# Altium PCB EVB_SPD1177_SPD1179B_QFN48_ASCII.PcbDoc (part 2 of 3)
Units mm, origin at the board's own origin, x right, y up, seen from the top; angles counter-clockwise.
Board outline 135 x 90 mm, 4 copper layers (Top Layer, GND, L3, Bottom Layer), stack 0.603 mm thick; 320 components, 157 nets, 728 pads, 938 vias.

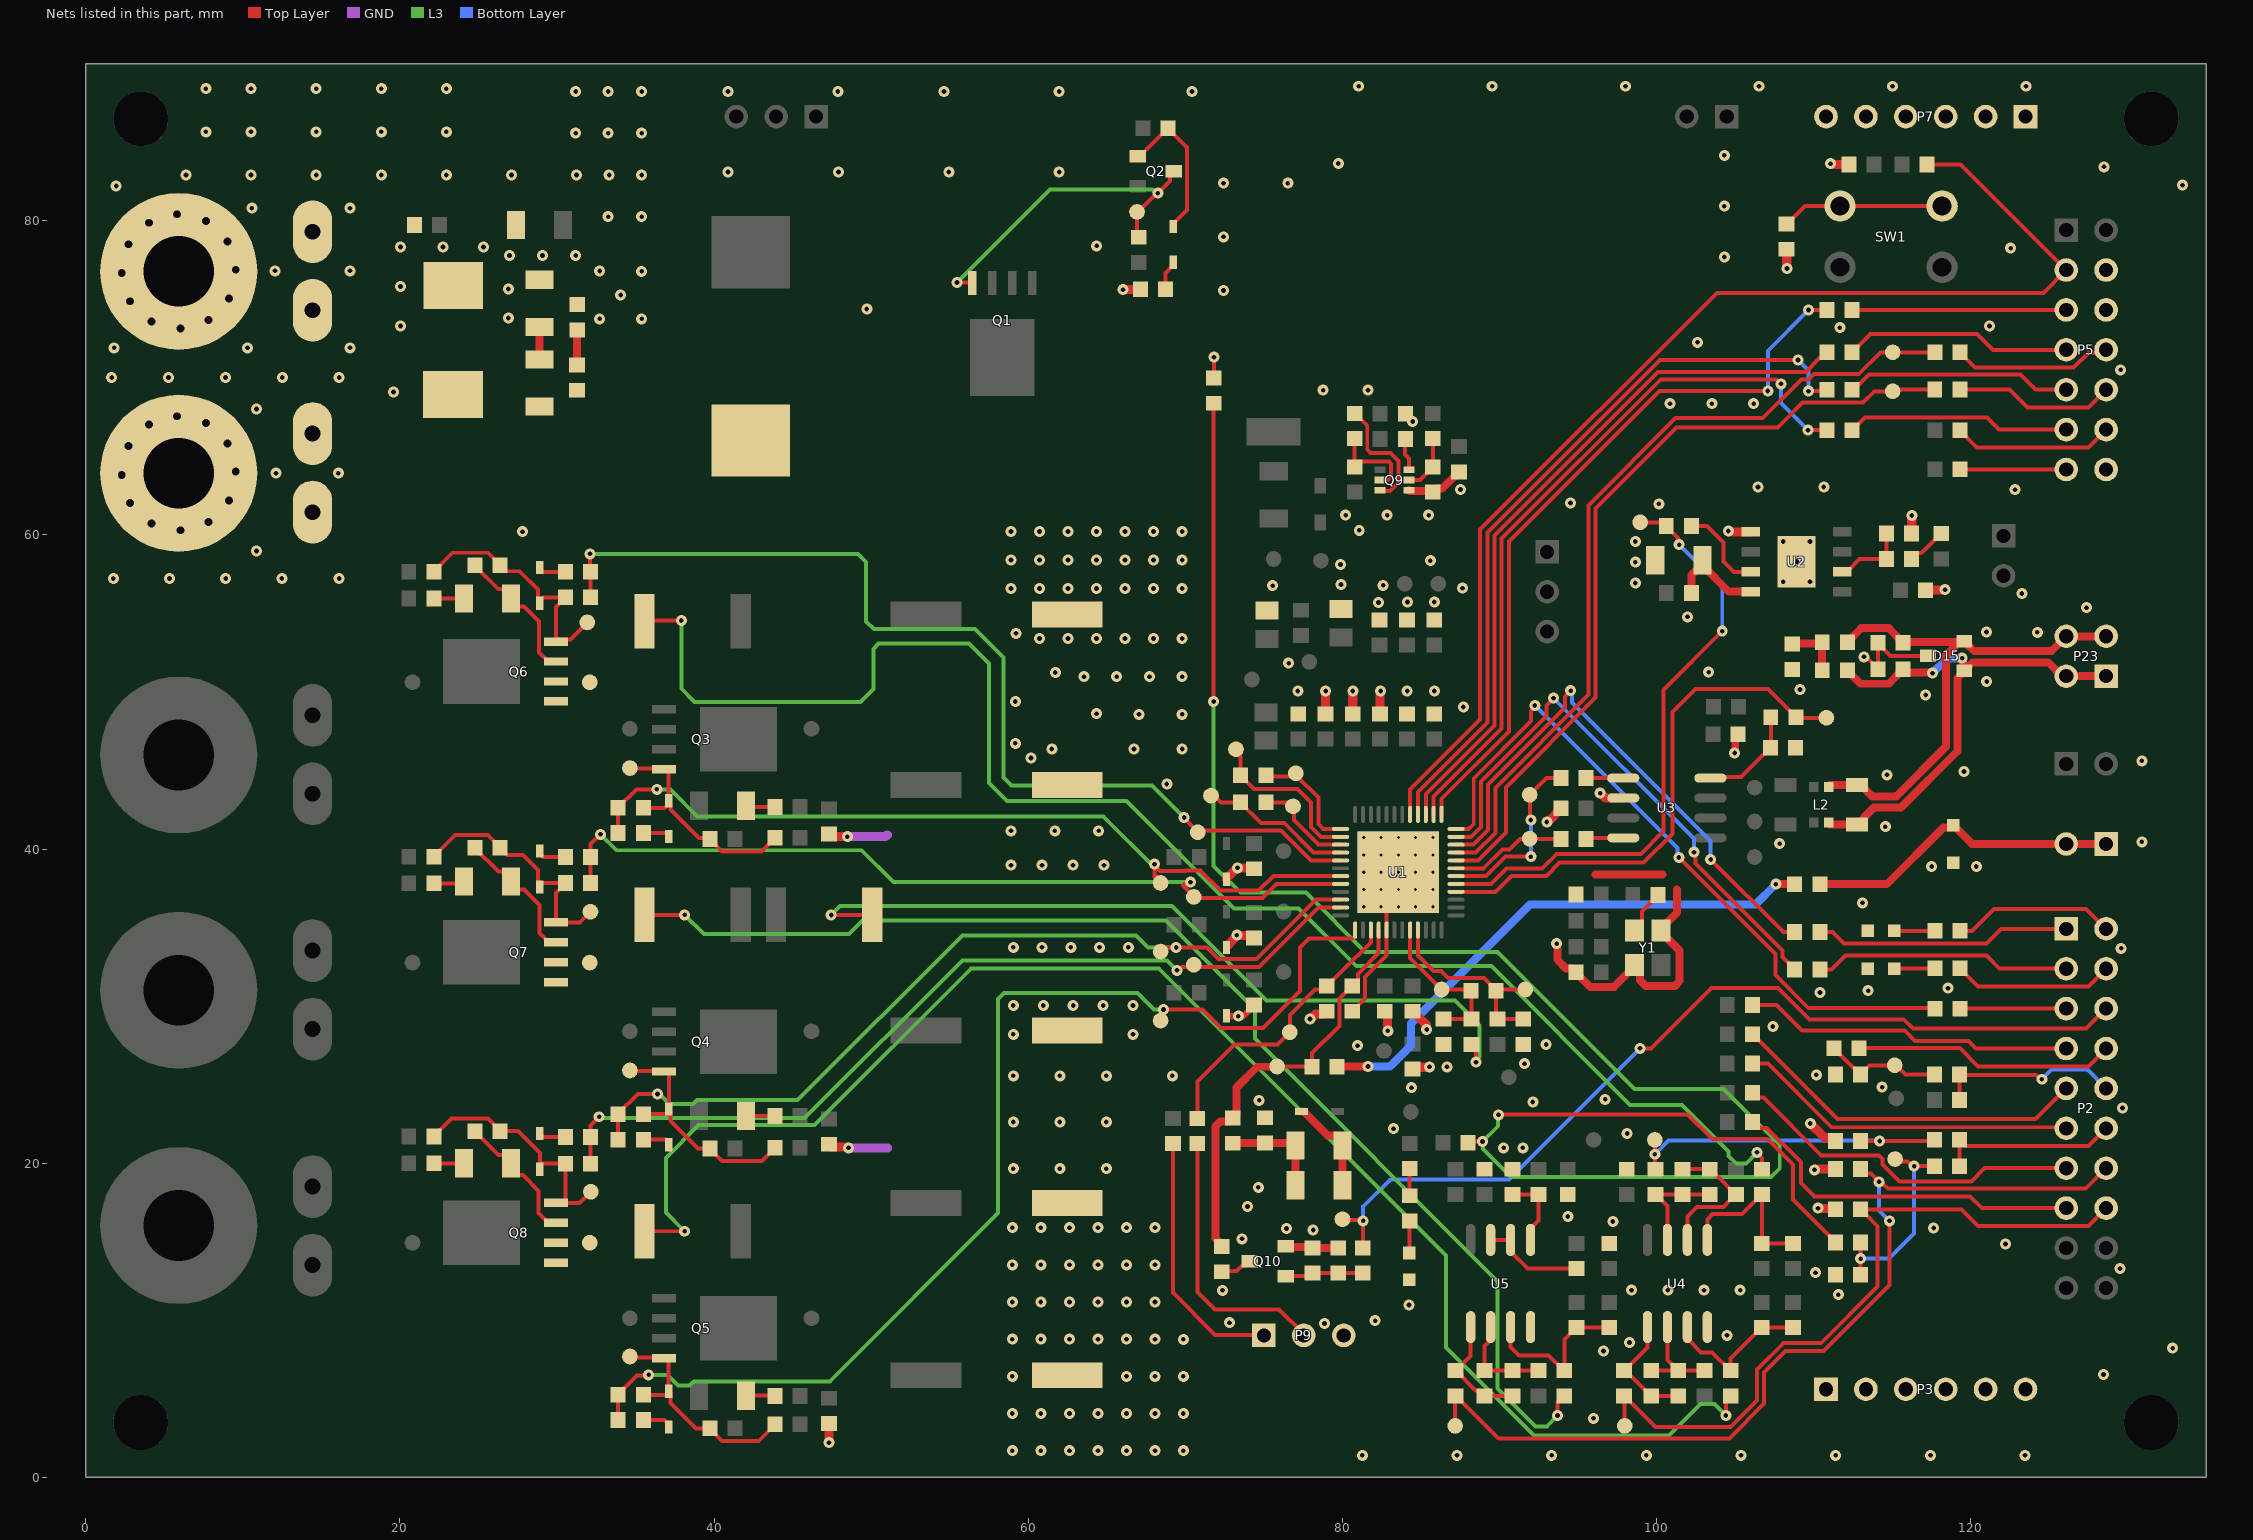
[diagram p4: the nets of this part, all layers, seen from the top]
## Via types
v1: diameter 0.7, hole 0.3, Top Layer to Bottom Layer, tented both sides, 691 vias
v2: diameter 0.5, hole 0.2, Top Layer to Bottom Layer, tented both sides, 154 vias
v3: diameter 0.9, hole 0.5, Top Layer to Bottom Layer, 60 vias
v4: diameter 0.5, hole 0.2, Top Layer to Bottom Layer, 32 vias
v5: diameter 0.7, hole 0.3, Top Layer to Bottom Layer, 1 vias

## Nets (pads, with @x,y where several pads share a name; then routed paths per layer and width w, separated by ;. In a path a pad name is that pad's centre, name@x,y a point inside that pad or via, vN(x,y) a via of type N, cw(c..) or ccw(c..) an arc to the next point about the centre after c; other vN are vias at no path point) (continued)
CANLDOEN: CANLDOEN.1 R81.1 U1.5 | length 38.8
  Top Layer w0.254: U1.5@87.241,37.782 89.471,37.782 90.449,38.76 92.71,38.76 93.65,39.701 99.01,39.701 100.457,41.148 100.457,50.145 v1(104.188,53.876) ; CANLDOEN.1@98.958,60.808 100.394,60.808 R81.1@100.622,60.579 100.622,60.554 101.362,59.814 101.362,59.471 v1(101.448,59.385)
  Bottom Layer w0.254: v1(101.448,59.385) 104.188,56.645 v1(104.188,53.876)
CANRX: CANRX.1 R65.2 U1.7 | length 7.4
  Top Layer w0.254: U1.7@87.241,38.782 88.998,38.782 90.195,39.98 90.653,39.98 91.313,40.64 R65.2@93.917,40.64
CANSTB: CANSTB.1 R79.1 U1.4 | length 34.2
  Top Layer w0.254: U1.4@87.241,37.282 89.758,37.282 90.78,38.303 92.989,38.303 93.828,39.141 99.187,39.141 101.016,40.97 101.016,48.717 102.489,50.19 107.099,50.19 108.877,48.412 R79.1@108.877,48.387 108.902,48.362 CANSTB.1@110.82,48.362
CANTX: CANTX.1 R62.2 U1.6 | length 11.7
  Top Layer w0.254: U1.6@87.241,38.282 89.158,38.282 90.399,39.522 v1(91.999,39.522) ; v1(91.999,41.859) 91.961,41.897 91.961,43.396 91.91,43.447 92.989,44.526 R62.2@93.917,44.526
  Bottom Layer w0.254: v1(91.999,39.522) v1(91.999,41.859)
CFBOT0: C50.1 CFBOT0.1 U1.26 | length 10.7
  Top Layer w0.254: CFBOT0.1@73.228,46.355 73.228,46.153 73.53,45.852 C50.1@73.53,44.704 73.53,44.679 74.386,43.823 77.149,43.823 78.013,42.959 78.013,41.404 78.635,40.782 U1.26@79.891,40.782
CFBOT1: C45.2 CFBOT1.1 U1.28 | length 9.8
  Top Layer w0.254: CFBOT1.1@71.637,43.409 71.839,43.409 72.271,42.977 C45.2@73.53,42.977 73.53,42.952 74.826,41.656 76.302,41.656 78.176,39.782 U1.28@79.891,39.782
CFTOP0: C50.2 CFTOP0.1 U1.25 | length 7.2
  Top Layer w0.254: C50.2@75.13,44.704 75.206,44.628 77.124,44.628 78.47,43.282 78.47,41.596 78.784,41.282 U1.25@79.891,41.282
CFTOP1: C45.1 CFTOP1.1 U1.27 | length 6.4
  Top Layer w0.254: C45.1@75.13,42.977 76.602,42.977 CFTOP1.1@76.858,42.721 ; CFTOP1.1@76.86,42.723 76.929,42.655 76.929,41.842 78.489,40.282 U1.27@79.891,40.282
D2SOUT: P2.8 R122.2 | length 16.7
  Top Layer w0.254: R122.2@112.89,27.33 119.318,27.33 120.474,26.174 127.495,26.174 P2.8@128.626,27.305
FB: R56.1 R57.2 U2.2 | length 4.8
  Top Layer w0.254: U2.2@111.823,57.658 112.123,57.658 112.936,58.471 R56.1@114.643,58.471 R57.2@114.643,60.096
GND: C1.2 C2.1 C5.2 C6.2 C7.1 C8.1 C10.2 C11.1 C12.1 C13.1 C14.2 C15.2 C16.1 C17.1 C18.1 C19.1 C23.1 C24.1 C29.1 C30.1 C31.1 C32.1 C33.1 C34.1 C35.1 C36.1 C37.1 C38.1 C39.1 C40.1 C41.1 C44.1 C52.1 C53.1 C54.1 C55.1 C57.1 C58.1 C61.1 C62.1 C63.1 C64.1 C70.1 C71.1 C72.1 C73.1 C74.1 C77.1 C78.1 C80.1 C81.1 C83.1 C84.1 C90.1 D1.1 D3.2 D4.2 D5.2 D13.2 D14.2 D15.3 D17.2 D18.1 P3.1 P3.2 P3.3 P3.4 P3.5 P3.6 P5.4 P5.6 P5.14 P6.1 P7.1 P7.2 P7.3 P7.4 P7.5 P7.6 P9.3 pad.1@5.918,76.784 Q9.1 Q10.2 R7.1 R9.2 R11.1 R55.1 R57.1 R58.1 R61.1 R85.2 R94.1 R98.2 R99.1 R109.2 U1.41 U1.49 U2.5 U2.9 U3.2 U4.4 U5.4 Y1.2 Y1.4 | length 139.9
  Top Layer w0.254: v1(47.459,35.808) 50,35.808 R55.1@50.005,35.814 ; R109.2@71.806,69.99 71.831,70.015 v1(71.831,71.323) ; C78.1@80.629,29.68 80.654,29.68 81.002,30.028 81.002,30.053 81.442,30.493 81.442,31.868 82.816,33.242 U1.41@82.816,34.857 82.816,37.782 v4(83.566,38.532) ; R98.2@84.01,67.716 84.482,67.245 v1(84.482,67.22) ; R58.1@88.224,27.572 88.519,27.276 88.516,27.274 v1(88.516,26.44) ; v1(113.208,52.248) 113.293,52.162 113.42,52.162 C62.1@114.097,51.485 ; C62.1@114.097,51.46 C62.1@114.097,51.485 ; C54.1@114.097,53.137 C54.1@114.097,53.112 ; D15.3@117.29,52.299 114.91,52.299 C54.1@114.097,53.112 ; C62.1@114.097,51.485 C54.1@114.097,53.112
  Top Layer w0.4: D3.2@72.628,29.391 72.656,29.362 v1(73.381,29.362) 73.679,29.362 C19.1@74.381,30.064
  Top Layer w0.508: Q10.2@76.403,14.719 76.46,14.662 78.048,14.662 C80.1@78.105,14.605 R94.1@79.731,14.605 ; Q9.1@84.232,62.85 84.276,62.806 85.687,62.806 R99.1@85.765,62.728 85.986,62.949 86.352,62.949 87.181,63.777 87.181,63.802 87.402,64.023 C83.1@87.427,64.023 ; v1(93.647,33.983) 93.684,33.946 93.684,32.96 94.242,32.402 94.661,32.402 94.882,32.181 C12.1@94.882,32.156 ; C12.1@94.882,32.131 95.789,31.225 97.284,31.225 98.591,32.531 Y1.4@98.591,32.631 98.937,32.285 98.937,31.67 99.314,31.293 101.175,31.293 101.473,31.59 101.473,33.549 100.291,34.731 Y1.2@100.291,34.831 100.291,34.931 101.321,35.961 101.321,37.438 ; C13.1@94.882,37.084 C13.1@94.882,37.109 C13.1@94.882,37.134 ; 96.127,38.379 100.379,38.379 ; v1(104.978,46.126) 105.015,46.163 105.015,47.141 C61.1@105.194,47.32
  Top Layer w0.58: v1(47.32,2.21) C18.1@47.32,3.442 ; C16.1@47.32,21.212 47.505,21.027 48.485,21.027 48.532,20.98 v1(48.565,20.98) ; C17.1@47.32,40.964 47.469,40.815 48.466,40.815 v1(48.489,40.792) ; v1(66.04,75.616) 66.053,75.629 67.132,75.629 R7.1@67.145,75.641 ; D5.2@72.628,38.078 72.628,38.148 73.269,38.788 73.307,38.788 v1(73.33,38.811) 73.353,38.788 74.343,38.788 C24.1@74.381,38.751 ; D4.2@72.688,33.864 73.011,34.187 73.011,34.218 73.279,34.486 v1(73.279,34.519) 73.302,34.496 74.239,34.496 C23.1@74.381,34.354 ; v1(77.947,29.185) 77.979,29.185 78.29,29.495 78.818,29.495 C8.1@79.003,29.68 ; C37.1@78.93,48.603 78.937,48.609 78.937,50.057 v1(78.943,50.063) ; C36.1@80.661,48.603 80.666,48.608 80.666,50.059 v1(80.67,50.063) ; C33.1@82.32,54.637 C33.1@82.372,54.585 ; C84.1@82.398,48.603 82.398,49.986 82.443,50.031 v1(82.443,50.063) ; C7.1@82.703,29.68 82.876,29.507 82.876,28.452 v1(82.899,28.429) ; C40.1@84.464,25.997 84.581,26.114 85.524,26.114 v1(85.547,26.137) ; C41.1@84.464,29.68 84.489,29.68 85.345,28.825 85.345,28.545 v1(85.368,28.522) ; v1(93.015,41.732) 93.038,41.755 93.101,41.755 93.917,42.571 C58.1@93.917,42.596 ; v1(96.418,43.561) 96.451,43.561 96.754,43.258 97.886,43.258 U3.2@97.888,43.256 ; v1(104.572,60.249) 104.604,60.249 104.655,60.198 U2.5@106.007,60.198 ; R9.2@108.28,78.194 108.293,78.181 108.293,76.975 v1(108.306,76.962) ; v1(109.796,22.534) 110.708,21.622 111.207,21.622 111.392,21.437 C63.1@111.392,21.412 ; v1(110.058,19.583) 110.091,19.583 110.141,19.634 C81.1@111.392,19.634 ; v1(110.287,17.145) 110.31,17.122 111.339,17.122 C64.1@111.392,17.069 ; v1(111.074,83.642) 111.107,83.642 111.157,83.591 R11.1@112.255,83.591 ; R57.1@116.243,60.096 116.249,60.103 116.249,61.233 v1(116.256,61.239) ; C44.1@117.132,56.49 117.145,56.502 118.351,56.502 v1(118.364,56.515)
  GND w0.58: v1(48.489,40.792) 50.927,40.792 51.029,40.894 ; v1(48.565,20.98) 51.054,20.98
  L3 w0.254: v1(47.459,35.808) 48.024,36.373 69.153,36.373 75.172,30.353 87.161,30.353 88.748,28.767 88.748,26.792 88.516,26.561 v1(88.516,26.44)
  other v1: 81.272,1.401 87.3,1.401 93.328,1.401 99.357,1.401 105.385,1.401 111.413,1.401 117.441,1.401 123.469,1.401 58.991,1.702 60.808,1.702 62.624,1.702 64.44,1.702 66.256,1.702 68.072,1.702 69.875,1.702 95.987,3.759 58.991,4.068 60.808,4.068 62.624,4.068 64.44,4.068 66.256,4.068 68.072,4.068 69.875,4.068 58.991,6.435 66.256,6.435 68.072,6.435 69.875,6.435 128.465,6.558 96.622,8.052 132.867,8.23 98.289,8.592 58.991,8.801 60.808,8.801 62.624,8.801 64.44,8.801 66.256,8.801 68.072,8.801 69.875,8.788 104.487,9.049 78.867,9.804 72.822,9.855 82.093,9.982 84.244,10.977 58.991,11.168 60.808,11.168 62.624,11.168 64.44,11.168 66.256,11.168 68.072,11.168 111.574,11.638 72.365,11.913 98.416,11.919 100.719,11.919 103.022,11.919 105.325,11.919 110.126,13.035 129.507,13.289 58.991,13.534 60.808,13.534 62.624,13.534 64.44,13.534 66.256,13.534 68.072,13.534 122.225,14.859 73.616,15.192 78.146,15.745 76.445,15.846 117.645,15.879 58.991,15.9 60.808,15.9 62.624,15.9 64.44,15.9 66.256,15.9 68.072,15.9 97.223,16.286 94.353,16.616 73.965,17.247 74.651,18.466 59.055,19.66 62.014,19.66 64.973,19.66 90.272,20.98 91.491,20.98 98.137,21.901 83.261,22.2 59.055,22.624 62.014,22.631 64.973,22.624 129.667,23.52 92.126,23.901 74.701,24.003 96.73,24.068 84.404,24.816 114.368,24.846 59.055,25.571 62.014,25.571 64.973,25.571 69.173,25.571 110.177,25.633 86.665,26.137 91.592,26.34 80.967,27.487 92.981,27.563 59.055,28.212 66.675,28.212 107.409,28.706 59.055,30.048 60.96,30.048 62.865,30.048 64.77,30.048 66.675,30.048 110.406,30.865 113.479,30.992 118.559,31.145 129.583,33.685 59.055,33.749 60.884,33.749 62.713,33.749 64.541,33.749 66.37,33.749 113.124,36.58 117.518,38.892 120.363,38.892 58.903,38.982 60.878,38.982 62.854,38.982 64.83,38.982 107.847,40.347 130.902,40.462 58.903,41.166 61.697,41.166 64.491,41.166 114.571,41.432 68.826,44.146 114.673,44.734 119.575,44.937 130.902,45.618 60.173,45.796 61.503,46.373 66.735,46.373 69.799,46.373 59.182,46.736 67.056,48.583 69.799,48.583 64.351,48.621 87.706,49.047 59.182,49.403 117.137,49.814 77.165,50.063 84.125,50.063 85.852,50.063 109.144,50.165 121.023,50.677 63.551,50.978 65.634,50.978 67.716,50.978 69.799,50.978 61.731,51.241 103.319,51.262 76.581,51.841 60.719,53.416 62.535,53.416 64.351,53.416 66.167,53.416 67.983,53.416 69.799,53.416 59.229,53.743 124.249,53.802 121.006,53.823 101.973,54.792 127.373,55.376 82.296,55.702 84.15,55.728 85.852,55.728 123.257,56.28 58.903,56.591 60.719,56.591 62.535,56.591 64.351,56.591 66.167,56.591 67.983,56.591 69.799,56.591 87.655,56.617 75.565,56.769 82.601,56.794 79.908,56.845 98.654,56.947 108.066,57.026 109.768,57.026 79.883,58.115 98.654,58.268 108.917,58.309 85.598,58.369 58.903,58.407 60.719,58.407 62.535,58.407 64.351,58.407 66.167,58.407 67.983,58.407 69.799,58.407 98.654,59.588 108.066,59.592 109.768,59.592 58.903,60.223 60.719,60.223 62.535,60.223 64.351,60.223 66.167,60.223 67.983,60.223 69.799,60.223 81.077,60.3 80.213,61.265 82.855,61.265 85.496,61.265 100.146,61.982 94.53,62.033 87.526,62.893 122.825,62.884 106.467,63.061 110.658,63.061 100.854,68.358 103.521,68.358 106.188,68.358 78.783,69.219 81.628,69.219 129.557,70.515 1.809,71.914 10.293,71.914 16.821,71.914 102.616,72.263 111.671,73.197 20.041,73.304 121.201,73.309 32.715,73.762 35.393,73.762 26.899,73.812 49.725,74.392 34.054,75.286 72.433,75.569 26.899,75.667 20.041,75.819 35.393,76.784 12.045,76.816 16.821,76.816 32.715,76.81 104.318,77.699 26.975,77.8 29.083,77.8 31.191,77.8 122.547,78.262 20.041,78.334 22.746,78.334 25.324,78.334 64.364,78.413 72.433,78.986 33.259,80.262 35.393,80.262 10.572,80.804 16.821,80.804 104.318,80.937 1.93,82.22 133.494,82.275 72.433,82.402 76.53,82.402 6.378,82.92 10.523,82.92 14.668,82.92 18.813,82.92 22.958,82.92 27.103,82.92 31.248,82.92 33.32,82.92 35.393,82.92 40.894,83.112 47.921,83.112 54.949,83.112 61.976,83.112 128.491,83.443 79.748,83.647 104.318,84.176 31.191,85.579 33.259,85.579 35.393,85.579 7.645,85.669 10.523,85.669 14.668,85.669 18.813,85.669 22.958,85.669 31.191,88.237 33.259,88.237 35.393,88.24 40.894,88.24 47.879,88.24 54.635,88.24 61.976,88.24 70.434,88.24 7.645,88.417 10.523,88.417 14.668,88.417 18.813,88.417 22.958,88.417 81.043,88.57 89.539,88.57 98.034,88.57 106.529,88.57 115.025,88.57 123.52,88.57
  other v3: 6.02,73.152 4.19,73.588 7.822,73.689 2.823,74.88 9.115,75.056 2.286,76.683 9.55,76.886 2.722,78.512 9.013,78.688 4.014,79.879 7.646,79.981 5.817,80.416
  other v4: 81.366,36.332 82.466,36.332 83.566,36.332 84.666,36.332 85.766,36.332 81.366,37.432 82.466,37.432 83.566,37.432 84.666,37.432 85.766,37.432 81.366,38.532 82.466,38.532 84.666,38.532 85.766,38.532 81.366,39.632 82.466,39.632 83.566,39.632 84.666,39.632 85.766,39.632 81.366,40.732 82.466,40.732 83.566,40.732 84.666,40.732 85.766,40.732
HO_U: HOU.1 R24.2 R27.2 U1.37 | length 73.3
  Top Layer w0.254: R24.2@33.896,3.658 R27.2@33.896,5.258 33.896,5.283 35.108,6.495 35.806,6.495 v1(35.839,6.528) ; HOU.1@68.428,29.083 HOU.1@68.428,29.285 ; v1(68.616,29.79) 71.108,29.79 72.272,28.626 74.955,28.626 77.292,30.963 77.292,33.724 77.884,34.315 80.661,34.315 80.816,34.471 U1.37@80.816,34.857
  L3 w0.254: v1(35.839,6.528) 37.022,6.528 37.712,5.837 38.425,5.837 38.71,6.121 47.371,6.121 58.09,16.84 58.09,30.455 58.467,30.831 66.969,30.831 68.01,29.79 v1(68.616,29.79) v1@68.616,29.692
HO_V: HOV.1 R23.2 R26.2 U1.34 | length 56.2
  Top Layer w0.254: R23.2@33.896,21.504 R26.2@33.896,23.13 33.896,23.155 35.151,24.409 v1(36.398,24.409) ; HOV.1@68.428,33.477 68.682,33.731 v1(69.418,33.731) 71.374,33.731 72.111,32.995 74.537,32.995 78.325,36.782 U1.34@79.891,36.782
  L3 w0.254: v1(36.398,24.409) 36.519,24.409 37.154,23.774 38.659,23.774 38.913,24.028 45.325,24.028 55.807,34.51 66.861,34.51 67.64,33.731 v1(69.418,33.731)
HO_W: HOW.1 R22.2 R25.2 U1.31 | length 53.3
  Top Layer w0.254: R22.2@33.896,41.028 R25.2@33.896,42.628 33.896,42.653 35.049,43.805 v1(36.357,43.805) ; v1(68.047,39.04) v1@68.047,38.957 ; HOW.1@68.428,37.846 HOW.1@68.285,37.989 ; U1.31@79.891,38.282 75.604,38.282 74.675,37.353 72.232,37.353 70.977,38.608 70.957,38.628 70.03,38.628 70.01,38.608 68.396,38.608 v1@68.047,38.957 ; 68.047,38.398 v1@68.047,38.957 ; 68.047,38.398 68.047,38.227 HOW.1@68.285,37.989 ; 68.047,38.398 68.285,38.159 HOW.1@68.285,37.989
  L3 w0.254: v1(36.357,43.805) 36.378,43.785 37.215,43.785 38.937,42.062 64.805,42.062 68.03,38.837 68.047,38.853 v1(68.047,39.04)
IDC: C90.2 IDC.1 R86.1 R122.1 | length 7.5
  Top Layer w0.254: R122.1@111.29,27.33 111.29,27.305 112.569,26.027 112.644,26.027 C90.2@112.992,25.679 ; C90.2@112.992,25.654 C90.2@112.992,25.679 ; IDC.1@115.164,26.238 113.576,26.238 113.365,26.027 113.34,26.027 C90.2@112.992,25.679 ; IDC.1@115.292,26.213 115.851,25.654 R86.1@117.704,25.654
IO12: R3.2 U1.10 | length 35.2
  Top Layer w0.254: U1.10@87.241,40.282 88.336,40.282 89.281,41.226 89.281,44.12 94.183,49.022 94.183,49.717 94.539,50.073 v1(94.539,50.089) ; v1(103.454,39.345) 108.077,34.722 R3.2@108.801,34.722
  Bottom Layer w0.254: v1(94.539,50.089) 94.624,50.003 94.624,49.343 103.454,40.513 v1(103.454,39.345)
IO13: R2.2 U1.11 | length 35.6
  Top Layer w0.254: U1.11@87.241,40.782 88.19,40.782 88.824,41.416 88.824,44.309 92.989,48.475 92.989,49.149 v1(93.447,49.606) ; v1(102.385,39.803) 102.47,39.718 102.47,39.089 108.026,33.533 108.026,33.134 108.801,32.359 R2.2@108.801,32.334
  Bottom Layer w0.254: v1(93.447,49.606) 102.385,40.668 v1(102.385,39.803)
IO14: R6.2 U1.12 | length 45
  Top Layer w0.254: U1.12@87.241,41.282 88.043,41.282 88.367,41.605 88.367,44.499 92.024,48.156 92.024,48.794 92.258,49.028 v1(92.258,49.149) ; v1(101.422,39.472) 107.569,33.325 107.569,31.979 109.678,29.87 R6.2@117.729,29.87
  Bottom Layer w0.254: v1(92.258,49.149) 101.337,40.071 101.337,39.557 v1(101.422,39.472)
IU: C64.2 IU.1 P2.16 R73.1 | length 45.7
  Top Layer w0.254: R73.1@97.935,5.194 97.974,5.155 IU.1@97.974,3.277 ; R73.1@97.96,5.194 99.948,3.206 104.722,3.206 106.401,4.884 106.401,6.858 108.102,8.56 110.49,8.56 114.071,12.141 114.071,15.989 113.365,16.696 113.34,16.696 112.992,17.044 C64.2@112.992,17.069 119.42,17.069 120.474,16.014 127.495,16.014 P2.16@128.626,17.145
IUS+: C48.1 Q8.1 Q8.2 Q8.3 R47.2 R53.2 R75.2 S.1@32.08,14.935 | length 107.1
  Top Layer w0.254: C48.1@24.778,22.047 24.778,22.022 26.271,20.529 26.63,20.529 27.302,19.857 27.302,19.462 27.526,19.238 27.824,19.238 28.829,18.234 28.829,16.821 29.445,16.205 Q8.3@29.94,16.205 ; R53.2@35.567,15.672 v1(38.125,15.672) ; v1(104.419,3.937) 104.419,4.889 R75.2@104.725,5.194
  L3 w0.254: v1(38.125,15.672) 36.932,16.866 36.932,20.345 39.014,22.428 46.406,22.428 56.363,32.385 68.334,32.385 86.589,14.13 86.589,8.28 92.198,2.671 100.805,2.671 102.802,4.668 103.688,4.668 v1(104.419,3.937)
IV: C81.2 IV.1 P2.14 R90.1 | length 59.4
  Top Layer w0.254: IV.1@87.182,3.277 87.182,5.169 R90.1@87.208,5.194 87.233,5.194 89.955,2.472 104.635,2.472 106.858,4.695 106.858,6.669 108.227,8.038 110.633,8.038 114.833,12.239 v1(114.833,16.338) ; C81.2@112.992,19.634 113.288,19.338 113.656,19.338 v1(114.173,18.821) 114.294,18.821 114.725,18.39 127.33,18.39 P2.14@128.626,19.685
  Bottom Layer w0.254: v1(114.173,18.821) 114.173,16.998 v1(114.833,16.338)
IVS+: C47.1 Q7.1 Q7.2 Q7.3 R46.2 R52.2 R92.2 S.1@32.08,32.779 | length 88
  Top Layer w0.254: C47.1@24.778,40.08 24.778,40.055 26.271,38.562 26.63,38.562 27.078,38.114 R46.2@27.078,37.946 27.078,37.866 27.526,37.418 27.885,37.418 28.873,36.43 28.873,34.646 29.445,34.074 Q7.3@29.94,34.074 ; R52.2@35.567,35.814 v1(38.125,35.814) ; v1(93.701,3.937) 93.701,4.762 93.76,4.821 93.76,4.846 94.108,5.194 R92.2@94.133,5.194
  L3 w0.254: v1(38.125,35.814) 39.345,34.595 48.59,34.595 49.454,35.458 68.774,35.458 74.446,29.786 74.446,27.93 89.891,12.485 89.891,5.653 92.292,3.251 93.015,3.251 v1(93.701,3.937)
IW: C63.2 IW.1 R72.1 R103.1 | length 21.3
  Top Layer w0.254: IW.1@99.898,21.488 v1(99.898,20.574) 99.898,19.658 R72.1@99.935,19.621 ; C63.2@112.992,21.412 v1(114.208,21.412) 117.627,21.412 R103.1@117.704,21.488
  Bottom Layer w0.254: v1(99.898,20.574) 100.762,21.438 114.183,21.438 v1(114.208,21.412)
IWS+: C46.1 Q6.1 Q6.2 Q6.3 R45.2 R51.2 R74.2 S.1@32.08,50.622 | length 107.6
  Top Layer w0.254: C46.1@24.778,58.064 24.778,58.039 26.271,56.547 26.63,56.547 27.302,55.875 27.302,55.676 27.526,55.452 27.885,55.452 28.854,54.483 28.854,52.534 29.445,51.943 Q6.3@29.94,51.943 ; R51.2@35.357,54.559 v1(37.915,54.559) ; v1(106.401,20.701) 106.401,20.671 106.725,20.346 R74.2@106.725,19.621
  L3 w0.254: v1(37.915,54.559) 37.915,50.211 38.749,49.378 49.313,49.378 50.14,50.204 50.14,52.744 50.481,53.086 56.238,53.086 57.506,51.818 57.506,44.196 58.649,43.053 66.269,43.053 66.272,43.056 73.107,36.22 77.216,36.22 80.886,32.55 89.485,32.55 98.312,23.724 101.625,23.724 104.597,20.752 104.597,20.455 105.082,19.97 105.687,19.97 106.401,20.683 v1(106.401,20.701)
KL30: C3.2 C4.2 D1.2 L1.1 P1.1 pad.1@5.918,63.932
  other v1: 1.753,57.226 5.328,57.226 8.903,57.226 12.478,57.226 16.129,57.226 10.871,58.979 27.802,60.211 12.116,63.932 16.078,63.932 10.871,68.021 19.597,69.101 1.651,70.028 5.271,70.028 8.89,70.028 12.509,70.028 16.129,70.028
  other v3: 6.02,60.3 4.19,60.735 7.822,60.837 2.823,62.028 9.115,62.204 2.286,63.83 9.55,64.033 2.722,65.66 9.013,65.836 4.014,67.027 7.646,67.128 5.817,67.564
LO_U: LOU.1 R36.2 R42.2 U1.35 | length 56.6
  Top Layer w0.254: R42.2@32.144,19.972 R36.2@32.144,21.674 32.144,22.415 v1(32.69,22.962) ; v1(69.469,32.283) 69.59,32.283 69.803,32.496 70.402,32.496 LOU.1@70.545,32.639 70.686,32.498 74.687,32.498 78.471,36.282 U1.35@79.891,36.282
  L3 w0.254: v1(32.69,22.962) 32.766,22.885 45.771,22.885 55.804,32.918 68.834,32.918 v1(69.469,32.283)
LO_V: LOV.1 R35.2 R41.2 U1.32 | length 53.5
  Top Layer w0.254: R41.2@32.144,37.845 R35.2@32.144,39.496 32.144,40.322 v1(32.766,40.945) ; v1(70.333,37.897) 70.089,37.897 69.869,37.677 70.545,37.001 LOV.1@70.545,36.957 70.607,36.896 74.929,36.896 75.815,37.782 U1.32@79.891,37.782
  L3 w0.254: v1(32.766,40.945) 33.782,39.929 49.378,39.929 51.41,37.897 v1(70.333,37.897)
LO_W: LOW.1 R34.2 R40.2 U1.29 | length 65.4
  Top Layer w0.254: v1(32.106,58.801) 32.106,57.696 R34.2@32.144,57.658 R40.2@32.144,56.032 ; v1(69.926,42.012) 69.926,41.973 70.621,41.278 70.621,41.199 76.082,41.199 77.999,39.282 U1.29@79.891,39.282
  L3 w0.254: v1(32.106,58.801) 49.174,58.801 49.682,58.293 49.682,54.499 50.181,54 56.617,54 58.42,52.197 58.42,44.575 58.951,44.044 67.894,44.044 v1(69.926,42.012)
MCU_FG: MCU_FG.1 P2.6 R91.2 | length 58.7
  Top Layer w0.254: MCU_FG.1@80.01,16.434 80.061,16.383 81.28,16.383 v1(81.331,16.332) 81.331,14.63 R91.2@81.305,14.605 ; v1(98.948,27.32) 99.659,27.32 103.505,31.166 107.735,31.166 109.742,29.159 115.742,29.159 116.327,28.575 127.356,28.575 P2.6@128.626,29.845
  Bottom Layer w0.254: v1(81.331,16.332) 81.331,17.247 83.058,18.974 90.602,18.974 v1(98.948,27.32)
MON: C8.2 MON.1 R78.1 U1.39 | length 18.5
  Top Layer w0.254: R78.1@70.764,22.847 70.764,25.197 73.127,27.559 75.87,27.559 MON.1@76.657,28.346 76.657,29.439 78.271,31.053 78.776,31.053 C8.2@79.003,31.28 79.028,31.28 80.083,32.334 80.086,32.334 81.816,34.064 U1.39@81.816,34.857
NetC2_2: C2.2 C3.1 | length 2.1
  Top Layer w0.508: C3.1@28.88,71.172 C2.2@28.88,73.252
NetC4_1: C4.1 C34.2 | length 2.3
  Top Layer w0.508: C4.1@31.267,70.815 31.28,70.828 31.28,73.05 C34.2@31.293,73.063
NetC9_1: C9.1 D2.1 Q2.1 | length 9.8
  Top Layer w0.254: Q2.1@66.973,84.11 67.098,84.11 68.518,85.53 68.549,85.53 C9.1@68.897,85.878 ; C9.1@68.897,85.903 C9.1@68.897,85.878 ; D2.1@69.24,79.648 69.24,79.838 70.103,80.701 70.103,84.673 C9.1@68.897,85.878
NetC20_1: C20.1 R32.1 | length 1.9
  Top Layer w0.254: R32.1@42.038,42.755 42.115,42.679 C20.1@43.879,42.679
NetC21_1: C21.1 R33.1 | length 1.8
  Top Layer w0.254: R33.1@42.038,23.003 C21.1@43.879,23.003
NetC22_1: C22.1 R37.1 | length 1.9
  Top Layer w0.254: R37.1@42.038,5.207 43.853,5.207 C22.1@43.879,5.182
NetC25_1: C25.1 R45.1 | length 1.9
  Top Layer w0.254: C25.1@22.161,55.956 R45.1@24.078,55.956
NetC26_2: C26.2 C56.2 D6.2 G.1@34.646,45.161 Q3.4 R25.1 | length 14.9
  Top Layer w0.254: G.1@34.646,45.161 34.68,45.126 36.77,45.126 Q3.4@36.805,45.092 36.97,45.092 37.109,44.952 D6.2@37.109,43.082 D6.2@37.109,42.892 ; R25.1@35.496,42.628 36.845,42.628 D6.2@37.109,42.892 ; C56.2@43.879,40.723 43.879,40.698 43.023,39.842 40.518,39.842 39.711,40.649 39.711,40.699 39.031,40.699 37.212,42.518 37.212,42.789 D6.2@37.109,42.892
NetC27_2: C27.2 C68.2 D7.2 G.1@34.646,25.908 Q4.4 R26.1 | length 15.3
  Top Layer w0.254: G.1@34.646,25.908 34.678,25.876 36.772,25.876 Q4.4@36.805,25.843 36.99,25.843 37.129,25.703 37.129,23.477 D7.2@37.109,23.457 ; R26.1@35.496,23.13 36.972,23.13 37.109,23.267 D7.2@37.109,23.354 ; D7.2@37.212,23.267 37.212,22.697 38.964,20.946 C27.2@39.738,20.946 39.738,20.921 40.518,20.141 43.048,20.141 43.879,20.971 C68.2@43.879,20.996
NetC28_2: C28.2 C69.2 D8.2 G.1@34.646,7.696 Q5.4 R27.1 | length 15.2
  Top Layer w0.254: G.1@34.646,7.696 34.696,7.645 36.754,7.645 Q5.4@36.805,7.595 36.97,7.595 37.109,7.455 D8.2@37.109,5.483 ; R27.1@35.496,5.258 37.006,5.258 37.109,5.361 D8.2@37.109,5.483 ; C69.2@43.879,3.378 43.879,3.353 42.845,2.319 40.518,2.319 39.738,3.099 C28.2@39.738,3.124 38.837,3.124 37.212,4.748 37.212,5.38 D8.2@37.109,5.483
NetC42_1: C42.1 R46.1 | length 2
  Top Layer w0.254: C42.1@22.161,37.819 23.951,37.819 R46.1@24.078,37.946
NetC43_1: C43.1 R47.1 | length 1.9
  Top Layer w0.254: C43.1@22.161,19.998 R47.1@24.078,19.998
NetC46_2: C46.2 C75.2 D9.2 G.1@31.928,54.432 Q6.4 R40.1 | length 16.3
  Top Layer w0.254: C75.2@22.161,57.658 22.161,57.683 23.348,58.869 25.598,58.869 26.378,58.089 C46.2@26.378,58.064 26.378,58.039 26.726,57.691 27.627,57.691 28.802,56.516 28.802,55.947 D9.2@28.905,55.844 ; D9.2@28.905,55.654 D9.2@28.905,55.844 ; G.1@31.928,54.432 30.848,53.353 30.08,53.353 Q6.4@29.94,53.213 29.94,55.404 30.544,56.007 R40.1@30.544,56.032 29.093,56.032 D9.2@28.905,55.844
NetC47_2: C47.2 C76.2 D10.2 G.1@32.131,36.017 Q7.4 R41.1 | length 16.2
  Top Layer w0.254: C76.2@22.161,39.521 22.161,39.546 23.5,40.885 25.598,40.885 26.378,40.105 C47.2@26.378,40.08 ; C47.2@26.378,40.055 26.809,39.624 27.838,39.624 28.802,38.66 D10.2@28.802,37.7 ; D10.2@28.905,37.597 28.905,37.742 29.008,37.845 R41.1@30.544,37.845 30.544,37.82 29.94,37.216 Q7.4@29.94,35.344 31.458,35.344 G.1@32.131,36.017
NetC48_2: C48.2 C79.2 D11.2 G.1@32.156,18.186 Q8.4 R42.1 | length 16
  Top Layer w0.254: C79.2@22.161,21.7 22.161,21.725 23.289,22.852 25.598,22.852 26.378,22.072 C48.2@26.378,22.047 27.508,22.047 28.905,20.65 D11.2@28.905,19.81 ; D11.2@28.905,19.62 D11.2@28.905,19.81 ; Q8.4@29.94,17.475 Q8.4@30.404,17.475 ; G.1@32.156,18.186 31.445,17.475 Q8.4@30.404,17.475 ; D11.2@28.905,19.81 29.068,19.972 R42.1@30.544,19.972 30.544,17.615 Q8.4@30.404,17.475
NetC54_2: C54.2 D15.2 L2.4 P23.3 P23.4 R59.2 R60.2 | length 33.6
  Top Layer w0.508: R59.2@110.97,43.961 110.97,43.986 111.058,44.074 L2.4@112.771,44.074 113.021,44.074 113.737,43.358 115.265,43.358 118.44,46.533 118.44,52.349 D15.2@119.193,53.103 ; R60.2@112.154,53.162 112.154,53.187 113.035,54.069 114.79,54.069 115.697,53.162 C54.2@115.697,53.137 115.753,53.193 119.534,53.193 D15.2@119.59,53.249 ; D15.2@119.836,53.003 120.235,52.603 125.136,52.603 P23.4@126.086,53.553 P23.3@128.626,53.553
NetC55_2: C55.2 R49.2 U2.8 | length 6.2
  Top Layer w0.508: R49.2@102.222,56.312 102.222,57.451 102.52,57.749 102.601,57.749 C55.2@102.922,58.07 ; C55.2@102.922,58.395 C55.2@102.922,58.07 ; U2.8@106.007,56.388 104.604,56.388 C55.2@102.922,58.07
NetC57_2: C57.2 R60.1 R63.1 | length 3.7
  Top Layer w0.508: C57.2@108.636,53.048 108.693,53.105 110.496,53.105 R60.1@110.554,53.162 R63.1@110.554,51.384
NetC59_1: C59.1 R68.1 R73.2 U4.1 | length 7.5
  Top Layer w0.254: U4.1@99.427,9.572 99.427,8.261 97.96,6.794 R73.2@97.935,6.794 98.283,6.446 98.385,6.446 99.637,5.194 C59.1@99.662,5.194 R68.1@101.389,5.194
NetC59_2: C59.2 R68.2 R71.1 U4.2 | length 6.4
  Top Layer w0.254: C59.2@99.662,6.794 R68.2@101.364,6.794 ; U4.2@100.697,9.572 100.697,7.462 R68.2@101.364,6.794 ; R71.1@103.057,6.794 R68.2@101.389,6.794 R68.2@101.364,6.794
NetC60_1: C60.1 R69.1 R72.2 U4.7 | length 6.7
  Top Layer w0.254: R72.2@99.935,18.021 R72.2@99.96,18.021 ; U4.7@100.697,15.117 100.697,17.284 R72.2@99.96,18.021 ; R69.1@103.389,18.021 C60.1@101.662,18.021 R72.2@99.96,18.021
NetC60_2: C60.2 R69.2 R70.1 U4.6 | length 9.2
  Top Layer w0.254: C60.2@101.662,19.621 R69.2@103.389,19.621 103.737,19.273 103.78,19.273 R70.1@105.032,18.021 ; U4.6@101.967,15.117 101.967,16.623 102.565,17.221 104.257,17.221 104.684,17.648 104.684,17.673 R70.1@105.032,18.021 ; R70.1@105.057,18.021 R70.1@105.032,18.021
NetC62_2: C62.2 D15.1 L2.3 P23.1 P23.2 R63.2 R67.2 | length 33.7
  Top Layer w0.508: R67.2@110.97,41.688 110.97,41.663 111.058,41.575 L2.3@112.771,41.575 113.021,41.575 113.217,41.77 113.217,42.02 113.843,42.647 115.57,42.647 119.151,46.228 119.151,50.905 D15.1@119.344,51.098 ; R63.2@112.154,51.384 112.154,51.359 112.984,50.529 114.79,50.529 115.697,51.435 C62.2@115.697,51.46 ; C62.2@115.918,51.228 115.918,51.243 117.54,51.243 v1(117.577,51.206) ; v1(119.465,52.161) 119.502,52.124 119.502,51.437 D15.1@119.59,51.349 ; D15.1@119.836,51.595 120.134,51.892 124.938,51.892 125.817,51.013 P23.1@128.626,51.013
  Bottom Layer w0.508: v1(117.577,51.206) 118.494,52.124 119.428,52.124 v1(119.465,52.161) v1@119.434,52.191
NetC65_2: C65.2 R74.1 R76.2 U4.5 | length 10.6
  Top Layer w0.254: U4.5@103.237,15.117 103.237,16.42 103.581,16.764 105.443,16.764 106.7,18.021 R74.1@106.725,18.021 106.705,18.002 R76.2@106.705,14.897 C65.2@108.687,14.897
NetC66_2: C66.2 R75.1 R77.2 U4.3 | length 9.9
  Top Layer w0.254: U4.3@101.967,9.572 101.967,8.843 102.849,7.961 103.534,7.961 104.7,6.794 R75.1@104.725,6.794 104.725,7.582 106.68,9.538 R77.2@106.705,9.538 C66.2@108.687,9.538
NetC67_1: C67.1 R80.1 R90.2 U5.1 | length 7.5
  Top Layer w0.254: R90.2@87.208,6.794 R90.2@87.233,6.794 ; U5.1@88.173,9.572 88.173,7.735 R90.2@87.233,6.794 ; R80.1@90.84,5.194 C67.1@89.057,5.194 88.709,5.542 88.485,5.542 R90.2@87.233,6.794
NetC67_2: C67.2 R80.2 R89.1 U5.2 | length 6.4
  Top Layer w0.254: U5.2@89.443,9.572 89.443,8.753 89.057,8.367 C67.2@89.057,6.794 R80.2@90.84,6.794 R89.1@92.491,6.794
NetC77_2: C77.2 R4.1 R83.1 R111.2 | length 6.4
  Top Layer w0.508: R111.2@73.025,21.273 73.038,21.285 75.07,21.285 C77.2@75.082,21.298 R83.1@76.846,21.298 ; R4.1@77.011,18.593 R83.1@77.011,21.133
NetC80_2: C80.2 Q10.1 R91.1 R94.2 | length 5
  Top Layer w0.254: Q10.1@76.403,12.819 77.919,12.819 C80.2@78.105,13.005 R94.2@79.731,13.005 R91.1@81.305,13.005
NetC82_2: C82.2 R92.1 R95.2 U5.3 | length 10.5
  Top Layer w0.254: U5.3@90.713,9.572 90.713,8.296 91.237,7.772 93.13,7.772 94.108,6.794 R92.1@94.133,6.794 94.133,8.792 94.879,9.538 R95.2@94.904,9.538 C82.2@96.987,9.538
NetD2_2: D2.2 R7.2 | length 1.9
  Top Layer w0.254: R7.2@68.745,75.641 68.745,76.683 69.24,77.178 D2.2@69.24,77.368
NetD6_1: D6.1 R22.1 | length 1.8
  Top Layer w0.254: R22.1@35.496,41.028 37.006,41.028 37.109,40.925 D6.1@37.109,40.802
NetD7_1: D7.1 R23.1 | length 1.9
  Top Layer w0.254: R23.1@35.496,21.504 36.972,21.504 37.109,21.367 D7.1@37.109,21.177
NetD8_1: D8.1 R24.1 | length 1.9
  Top Layer w0.254: R24.1@35.496,3.658 36.845,3.658 37.109,3.393 D8.1@37.109,3.203
NetD9_1: D9.1 R34.1 | length 1.9
  Top Layer w0.254: D9.1@28.905,57.934 28.905,57.761 29.008,57.658 R34.1@30.544,57.658
NetD10_1: D10.1 R35.1 | length 1.9
  Top Layer w0.254: D10.1@28.905,39.877 28.905,39.687 29.096,39.496 R35.1@30.544,39.496
NetD11_1: D11.1 R36.1 | length 1.8
  Top Layer w0.254: D11.1@28.905,21.9 28.905,21.777 29.008,21.674 R36.1@30.544,21.674
NetD13_1: D13.1 R102.2 | length 2.6
  Top Layer w0.254: D13.1@115.151,32.385 115.176,32.41 R102.2@117.729,32.41
NetD14_1: D14.1 R101.2 | length 2.6
  Top Layer w0.254: D14.1@115.176,34.798 R101.2@117.729,34.798
NetD16_1: D16.1 R4.2 R83.2 | length 6.2
  Top Layer w0.508: D16.1@77.406,23.292 77.548,23.292 79.061,21.779 79.69,21.779 80.011,21.458 R83.2@80.011,21.133 R4.2@80.011,18.593
NetD17_1: D17.1 R105.2 | length 2.1
  Top Layer w0.254: D17.1@84.261,14.287 84.287,14.313 R105.2@84.287,16.332
NetP2_1: P2.1 R3.1 | length 16.4
  Top Layer w0.254: R3.1@110.401,34.722 111.214,34.722 111.943,33.993 121.014,33.993 121.945,34.925 P2.1@126.086,34.925
NetP2_2: P2.2 R101.1 | length 10.4
  Top Layer w0.254: R101.1@119.329,34.798 120.088,34.798 121.485,36.195 127.356,36.195 P2.2@128.626,34.925
NetP2_3: P2.3 R2.1 | length 16.4
  Top Layer w0.254: R2.1@110.401,32.334 111.15,32.334 112.031,33.215 121.023,33.215 121.853,32.385 P2.3@126.086,32.385
NetP2_4: P2.4 R102.1 | length 10.3
  Top Layer w0.254: R102.1@119.329,32.41 119.329,32.385 120.46,31.254 127.495,31.254 P2.4@128.626,32.385
NetP2_5: P2.5 R6.1 | length 6.8
  Top Layer w0.254: R6.1@119.329,29.845 P2.5@126.086,29.845
NetP2_7: P2.7 R8.1 | length 21.1
  Top Layer w0.254: R8.1@106.108,30.074 107.645,30.074 109.271,28.448 115.807,28.448 116.467,27.788 119.863,27.788 120.345,27.305 P2.7@126.086,27.305
NetP2_9: P2.9 R10.1 | length 23
  Top Layer w0.254: R10.1@106.108,28.213 106.108,28.188 106.456,27.84 106.481,27.84 111.512,22.809 124.13,22.809 P2.9@126.086,24.765
NetP2_10: P2.10 R86.2 R87.2 | length 11.8
  Top Layer w0.254: R87.2@119.304,24.028 R86.2@119.304,25.629 ; R86.2@119.304,25.654 R86.2@119.304,25.629 ; v1(124.536,25.349) 124.444,25.349 124.164,25.629 R86.2@119.304,25.629
  Bottom Layer w0.254: v1(124.536,25.349) 125.146,25.959 127.432,25.959 P2.10@128.626,24.765
NetP2_11: P2.11 R28.1 | length 21.7
  Top Layer w0.254: R28.1@106.108,26.352 107.091,26.352 111.15,22.293 126.017,22.293 P2.11@126.086,22.225
NetP2_12: P2.12 R103.2 R104.2 | length 11.6
  Top Layer w0.254: R104.2@119.304,19.812 R103.2@119.304,21.488 119.304,21.463 119.652,21.115 119.779,21.115 119.8,21.094 127.495,21.094 P2.12@128.626,22.225
NetP2_13: P2.13 R29.1 | length 22.9
  Top Layer w0.254: R29.1@106.108,24.492 106.418,24.183 106.805,24.183 110.49,20.498 114.173,20.498 114.384,20.287 114.384,19.936 115.473,18.847 120.05,18.847 120.888,19.685 P2.13@126.086,19.685
NetP2_15: P2.15 R30.1 | length 23
  Top Layer w0.254: R30.1@106.108,22.631 106.108,22.606 106.456,22.258 107.002,22.258 109.188,20.073 109.188,18.752 110.053,17.887 119.968,17.887 120.71,17.145 P2.15@126.086,17.145
NetP5_5: P5.5 R13.1 | length 13.6
  Top Layer w0.254: R13.1@112.458,74.32 112.468,74.33 P5.5@126.086,74.33
NetP5_7: P5.7 R14.1 | length 14.5
  Top Layer w0.254: R14.1@112.458,71.628 112.458,71.653 112.806,72.001 112.831,72.001 113.627,72.796 120.421,72.796 121.428,71.79 P5.7@126.086,71.79
NetP5_8: P5.8 R15.2 | length 10.2
  Top Layer w0.254: R15.2@119.329,71.628 119.329,71.603 120.269,70.663 123.41,70.663 123.414,70.659 126.554,70.659 127.495,71.599 128.435,71.599 P5.8@128.626,71.79
NetP5_9: P5.9 R16.1 | length 14.5
  Top Layer w0.254: R16.1@112.458,69.147 112.458,69.172 112.806,69.52 112.831,69.52 113.517,70.206 123.19,70.206 124.146,69.25 P5.9@126.086,69.25
NetP5_10: P5.10 R17.2 | length 10.3
  Top Layer w0.254: R17.2@119.316,69.266 122.483,69.266 123.63,68.119 127.495,68.119 P5.10@128.626,69.25
NetP5_11: P5.11 R18.1 | length 14.3
  Top Layer w0.254: R18.1@112.458,66.692 112.806,67.04 112.831,67.04 113.262,67.47 113.438,67.47 113.439,67.471 121.057,67.471 121.819,66.71 P5.11@126.086,66.71
NetP5_12: P5.12 R19.2 | length 10.2
  Top Layer w0.254: R19.2@119.329,66.667 119.329,66.642 120.392,65.579 127.495,65.579 P5.12@128.626,66.71
NetP5_13: P5.13 R20.1 | length 6.8
  Top Layer w0.254: R20.1@119.329,64.186 119.345,64.17 P5.13@126.086,64.17
NetP9_1: P9.1 R64.1 | length 16.4
  Top Layer w0.254: R64.1@69.215,21.247 69.215,11.76 71.907,9.068 74.981,9.068 P9.1@75.006,9.042
NetP9_2: P9.2 R78.2 | length 17.4
  Top Layer w0.254: R78.2@70.764,21.247 70.764,11.811 71.882,10.693 75.971,10.693 77.546,9.119 P9.2@77.546,9.042
NetQ1_4: Q1.4 Q2.3 R5.2 TP2.1 | length 21.6
  Top Layer w0.254: v1(55.474,76.073) 56.413,76.073 Q1.4@56.439,76.048 ; R5.2@67.031,78.956 66.929,79.057 TP2.1@66.929,80.569 66.992,80.569 68.186,81.763 v1(68.25,81.763) 69.015,82.527 69.015,82.901 Q2.3@69.273,83.16
  L3 w0.254: v1(55.474,76.073) 61.392,81.991 67.901,81.991 68.129,81.763 v1(68.25,81.763)
NetQ9_2: Q9.2 R97.2 R99.2 | length 3.7
  Top Layer w0.254: Q9.2@84.232,63.5 84.937,63.5 85.392,63.955 85.392,63.98 85.74,64.328 R99.2@85.765,64.328 R97.2@85.765,66.141
NetQ9_3: Q9.3 R88.2 | length 2.1
  Top Layer w0.254: R88.2@84.01,66.116 83.987,66.093 83.987,65.111 84.232,64.866 Q9.3@84.232,64.15
NetQ9_5: Q9.5 R93.2 R100.1 | length 5.8
  Top Layer w0.254: R100.1@80.781,65.954 R93.2@80.781,64.328 81.127,64.674 82.96,64.674 83.109,64.525 83.109,63.708 82.901,63.5 82.51,63.5 82.451,63.559 Q9.5@82.392,63.5
NetQ9_6: Q9.6 R100.2 | length 7.5
  Top Layer w0.254: R100.2@80.781,67.741 80.806,67.741 81.586,66.962 81.586,65.429 81.796,65.219 83.062,65.219 83.566,64.715 83.566,63.348 83.033,62.814 Q9.6@82.652,62.814 ; Q9.6@82.392,62.85 Q9.6@82.453,62.911
NetQ10_3: Q10.3 R84.2 | length 2.1
  Top Layer w0.254: R84.2@72.314,13.094 72.349,13.129 73.268,13.129 73.635,13.496 73.83,13.496 Q10.3@74.103,13.769
NetR9_1: R9.1 SW1.1 SW1.2 | length 10.4
  Top Layer w0.254: R9.1@108.28,79.794 108.305,79.794 109.455,80.944 SW1.1@111.685,80.944 SW1.2@118.185,80.944
NetR21_2: R21.2 R66.1 | length 34.8
  Top Layer w0.508: R66.1@79.667,26.137 79.68,26.149 81.597,26.149 81.636,26.111 v1(81.636,26.162) ; v1(107.594,37.77) R21.2@108.801,37.77
  Bottom Layer w0.508: v1(81.636,26.162) 83.033,26.162 84.366,27.495 84.366,28.892 91.948,36.474 106.299,36.474 v1(107.594,37.77)
NetR50_1: R50.1 R56.2 | length 2.6
  Top Layer w0.254: R56.2@116.243,58.471 116.243,58.496 116.591,58.844 116.871,58.844 118.11,60.084 R50.1@118.135,60.084
NetR61_2: R61.2 R79.2 U3.8 | length 6.6
  Top Layer w0.254: U3.8@103.433,44.526 103.497,44.59 105.385,44.59 106.879,46.084 106.904,46.084 107.252,46.432 R61.2@107.252,46.457 107.277,46.482 R79.2@107.277,48.387
NetR62_1: R62.1 U3.1 | length 2.4
  Top Layer w0.254: R62.1@95.517,44.526 U3.1@97.888,44.526
NetR65_1: R65.1 U3.4 | length 2.4
  Top Layer w0.254: R65.1@95.517,40.64 95.593,40.716 U3.4@97.888,40.716
NetR81_2: R81.2 U2.7 | length 5.7
  Top Layer w0.254: R81.2@102.222,60.579 103.208,60.579 104.267,59.52 104.267,58.318 104.927,57.658 U2.7@106.007,57.658
NetR82_2: R82.2 R85.1 U5.5 | length 4.8
  Top Layer w0.254: R85.1@90.84,18.021 R82.2@92.491,18.021 92.491,16.353 91.983,15.845 U5.5@91.983,15.117
NetR105_1: R105.1 R106.1 | length 1.7
  Top Layer w0.254: R105.1@84.287,17.932 R106.1@84.287,19.66
NetR107_1: R107.1 R108.1 R109.1 | length 123.9
  Top Layer w0.254: v1(71.806,49.403) R109.1@71.806,68.39 ; R107.1@87.998,21.311 88.072,21.384 v1(88.925,21.384) ; v1(89.941,23.089) 89.967,23.114 101.981,23.114 103.556,21.539 107.075,21.539 108.687,19.927 108.687,17.691 111.392,14.986 R108.1@111.392,14.961
  L3 w0.254: v1(71.806,49.403) 71.806,38.938 73.508,37.236 77.673,37.236 81.445,33.465 89.864,33.465 98.589,24.74 104.267,24.74 107.848,21.158 107.848,19.681 107.293,19.126 90.729,19.126 88.961,20.894 88.961,21.349 v1(88.925,21.384) 89.899,22.358 89.899,23.046 v1(89.941,23.089)
NetR110_2: R110.2 U5.6 U5.7 | length 6.6
  Top Layer w0.254: U5.7@89.443,15.117 U5.6@90.713,15.117 90.713,14.388 91.804,13.297 R110.2@94.904,13.297
NetR123_1: R123.1 Y1.3 | length 2.9
  Top Layer w0.254: Y1.3@98.591,34.831 99.064,35.304 99.064,36.034 100.089,37.059 R123.1@100.089,37.084
NTCAD: C73.2 NTCAD.1 R104.1 R108.2 | length 13.1
  Top Layer w0.254: C73.2@112.992,12.903 R108.2@112.992,14.961 R108.2@112.992,14.986 ; NTCAD.1@115.189,20.269 115.332,20.126 115.973,20.126 116.288,19.812 v1(116.408,19.812) R104.1@117.704,19.812
  Bottom Layer w0.254: v1(113.005,13.924) 114.812,13.924 116.408,15.519 v1(116.408,19.812)
PGAIN: C51.1 C53.2 PGAIN.1 R58.2 U1.44 | length 10.1
  Top Layer w0.254: U1.44@84.316,34.857 84.316,33.067 PGAIN.1@86.319,31.064 88.109,31.064 C51.1@88.186,30.988 88.224,30.95 R58.2@88.224,29.172 C53.2@86.446,29.172
PGAIP: C51.2 C52.2 PGAIP.1 R54.2 U1.45 | length 13
  Top Layer w0.254: U1.45@84.816,34.857 84.816,33.213 85.801,32.228 86.293,32.228 86.728,31.793 89.006,31.793 89.786,31.013 C51.2@89.786,30.988 ; C52.2@91.526,29.172 R54.2@89.875,29.172 89.786,29.261 C51.2@89.786,30.988 ; PGAIP.1@91.653,31.064 89.862,31.064 C51.2@89.786,30.988
PWM/LIN/IO: D18.2 P25.1 P25.2 R21.1 | length 20.3
  Top Layer w0.508: R21.1@110.401,37.77 114.656,37.77 118.271,41.385 118.751,41.385 D18.2@118.897,41.531 120.101,40.327 P25.2@126.086,40.327 P25.1@128.626,40.327
PWM/LIN_MCU: C78.2 PMU/LIN_MCU.1 R66. R84.1 R111.1 U1.40 | length 27
  Top Layer w0.254: R111.1@73.025,22.873 R111.1@73.262,23.11 ; PMU/LIN_MCU.1@75.844,26.162 78.042,26.162 R66.@78.067,26.137 78.067,27.012 79.808,28.753 79.808,30.484 80.604,31.28 C78.2@80.629,31.28 ; C78.2@80.764,31.28 80.985,31.5 80.985,32.057 82.316,33.389 U1.40@82.316,34.857
  Top Layer w0.508: R84.1@72.314,14.694 72.289,14.694 72.068,14.915 72.068,15.077 71.933,15.212 71.933,22.354 72.23,22.652 72.804,22.652 R111.1@73.025,22.873 ; R111.1@73.262,23.11 73.262,24.824 74.582,26.145 75.827,26.145 PMU/LIN_MCU.1@75.844,26.162
TCK/SWC: R16.2 U1.16 | length 47.6
  Top Layer w0.254: U1.16@84.816,42.207 84.816,43.647 89.23,48.061 89.23,60.152 100.224,71.145 v1(109.017,71.145) ; v1(109.677,69.159) 110.777,69.159 R16.2@110.858,69.24
  Bottom Layer w0.254: v1(109.017,71.145) 109.677,70.485 v1(109.677,69.159)
TDI: R13.2 U1.13 | length 47
  Top Layer w0.254: U1.13@86.316,42.207 86.316,43.207 90.602,47.493 90.602,59.583 100.188,69.17 v1(107.086,69.17) ; v1(109.677,74.32) R13.2@110.858,74.32
  Bottom Layer w0.254: v1(107.086,69.17) 107.086,71.73 v1(109.677,74.32)
TDO: R18.2 U1.14 | length 46.3
  Top Layer w0.254: U1.14@85.816,42.207 85.816,43.354 90.145,47.682 90.145,59.773 100.273,69.901 107.65,69.901 v1(107.923,69.628) ; v1(109.652,66.675) 110.85,66.675 R18.2@110.858,66.667
  Bottom Layer w0.254: v1(107.923,69.628) 107.923,68.404 v1(109.652,66.675)
TMS/SWD: R14.2 U1.15 | length 45.6
  Top Layer w0.254: U1.15@85.316,42.207 85.316,43.5 89.687,47.872 89.687,59.962 100.109,70.383 109.513,70.383 110.385,71.255 110.51,71.255 110.858,71.603 R14.2@110.858,71.628
TRSTn: P5.3 R12.1 U1.17 | length 75.8
  Top Layer w0.254: U1.17@84.316,42.207 84.316,43.794 88.773,48.251 88.773,60.341 103.845,75.413 124.628,75.413 P5.3@126.086,76.87 119.364,83.591 R12.1@117.234,83.591
UART_RX: R15.1 U1.9 UART_RX.1 | length 52.4
  Top Layer w0.254: U1.9@87.241,39.782 88.483,39.782 89.738,41.037 89.738,43.903 95.67,49.835 95.67,61.888 101.219,67.437 106.766,67.437 109.219,69.89 109.666,69.89 110.033,70.256 112.878,70.256 114.249,71.628 R15.1@117.729,71.628
UART_TX: R17.1 U1.8 UART_TX.1 | length 51.6
  Top Layer w0.254: U1.8@87.241,39.282 88.646,39.282 90.411,41.046 90.411,43.929 96.127,49.645 96.127,61.699 101.281,66.853 107.721,66.853 109.296,68.428 113.145,68.428 113.864,69.147 UART_TX.1@115.037,69.147 115.155,69.266 R17.1@117.716,69.266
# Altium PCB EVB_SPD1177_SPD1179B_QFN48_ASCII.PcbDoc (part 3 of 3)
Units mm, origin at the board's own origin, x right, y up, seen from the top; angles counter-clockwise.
Board outline 135 x 90 mm, 4 copper layers (Top Layer, GND, L3, Bottom Layer), stack 0.603 mm thick; 320 components, 157 nets, 728 pads, 938 vias.

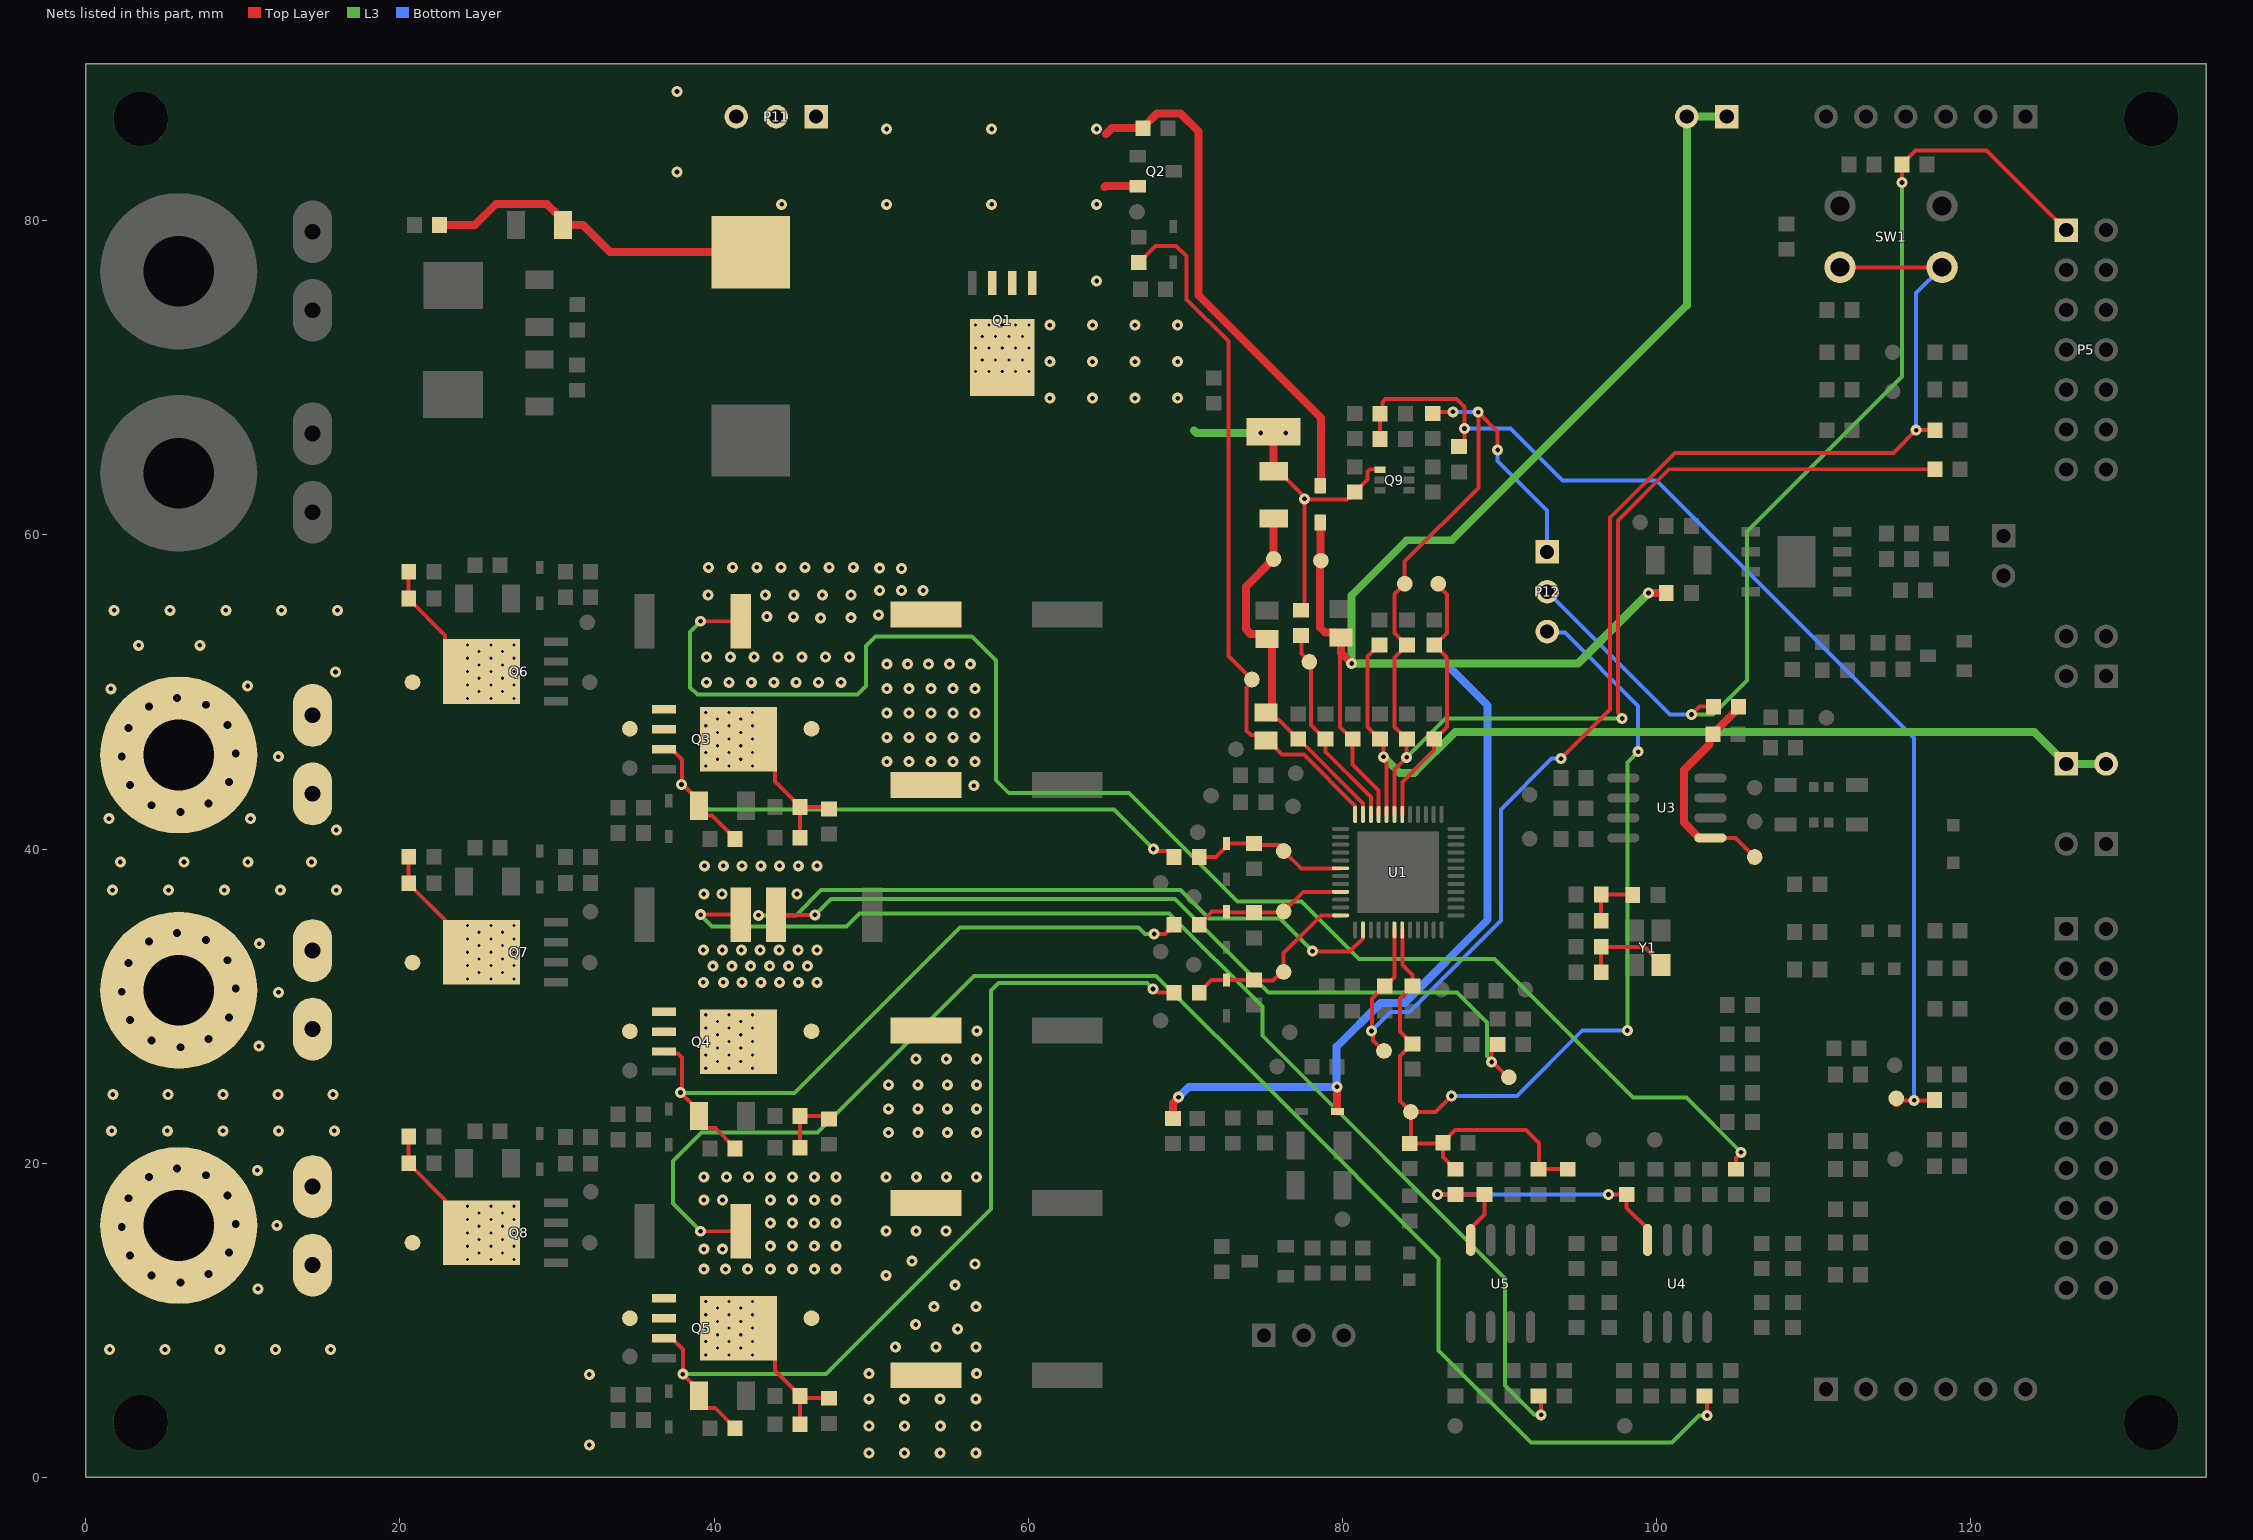
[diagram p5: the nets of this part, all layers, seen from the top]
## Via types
v1: diameter 0.7, hole 0.3, Top Layer to Bottom Layer, tented both sides, 691 vias
v2: diameter 0.5, hole 0.2, Top Layer to Bottom Layer, tented both sides, 154 vias
v3: diameter 0.9, hole 0.5, Top Layer to Bottom Layer, 60 vias
v4: diameter 0.5, hole 0.2, Top Layer to Bottom Layer, 32 vias
v5: diameter 0.7, hole 0.3, Top Layer to Bottom Layer, 1 vias

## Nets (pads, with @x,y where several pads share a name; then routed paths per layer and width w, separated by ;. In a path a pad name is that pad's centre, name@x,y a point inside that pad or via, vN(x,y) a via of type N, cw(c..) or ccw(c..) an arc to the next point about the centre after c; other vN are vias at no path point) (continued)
VBAT: C35.2 C36.2 D12.1 D16.2 P10.1 P10.2 R49.1 R64.2 U1.21 VBAT.1 | length 144.7
  Top Layer w0.254: C35.2@79.908,53.481 79.856,53.429 79.856,47.783 80.636,47.003 C36.2@80.661,47.003 80.661,45.383 82.316,43.728 U1.21@82.316,42.207
  Top Layer w0.508: R64.2@69.215,22.847 69.215,23.82 69.571,24.176 v1(69.571,24.206) ; D12.1@78.595,60.798 78.595,58.412 VBAT.1@78.638,58.369 78.588,58.318 78.588,54.1 78.885,53.802 79.587,53.802 C35.2@79.908,53.481 79.908,52.502 v1(80.594,51.816) ; v1(79.654,24.867) 79.654,23.324 D16.2@79.686,23.292 ; v1(99.492,56.312) R49.1@100.622,56.312
  L3 w0.508: v1(99.492,56.312) 94.996,51.816 v1(80.594,51.816) 80.594,56.159 84.099,59.665 86.97,59.665 101.93,74.625 P10.2@101.93,86.639 P10.1@104.47,86.639
  Bottom Layer w0.508: v1(69.571,24.206) 70.231,24.867 v1(79.654,24.867) ; v1@79.642,24.892 79.642,27.419 82.433,30.21 83.957,30.21 89.256,35.509 89.256,49.149 86.589,51.816 v1(80.594,51.816)
VBAT1: C9.2 C10.1 C11.2 D12.2 L1.2 P11.1 P11.2 P11.3 Q1.1 Q1.2 Q1.3 Q2.2 | length 56.7
  Top Layer w0.508: C11.2@22.517,79.731 24.77,79.731 26.102,81.062 29.373,81.062 30.059,80.377 30.38,80.056 C10.1@30.38,79.731 31.648,79.731 33.37,78.009 L1.2@42.342,78.009 ; 64.872,82.169 64.912,82.21 Q2.2@66.973,82.21 ; 64.948,85.522 65.329,85.903 C9.2@67.297,85.903 67.297,85.928 68.204,86.835 69.706,86.835 70.841,85.7 70.841,75.26 78.638,67.462 D12.2@78.638,63.143
  other v1: 64.364,76.175 44.304,81.051 50.99,81.051 57.677,81.051 64.364,81.051 37.643,83.112 50.99,85.852 57.677,85.852 64.364,85.852 37.643,88.24
VBAT_D: C1.1 C5.1 C6.1 C14.1 C15.1 C16.2 C17.2 C18.2 C20.2 C21.2 C22.2 C56.1 C68.1 C69.1 D.1 Q1.5 Q3.5 Q4.5 Q5.5 Q9.4 R39.2 R43.1 R93.1 VBAT_D.1 | length 45
  Top Layer w0.254: v2(42.443,7.804) 43.631,7.804 43.866,7.569 43.866,6.819 45.479,5.207 C22.2@45.479,5.182 ; v2(42.443,45.301) 43.631,45.301 43.866,45.066 43.866,44.316 45.479,42.704 C20.2@45.479,42.679 ; C69.1@45.479,3.378 C22.2@45.479,5.182 ; C68.1@45.479,20.996 C21.2@45.479,23.003 47.13,23.003 C16.2@47.32,22.812 ; C56.1@45.479,40.723 C20.2@45.479,42.679 ; C18.2@47.32,5.042 45.618,5.042 C22.2@45.479,5.182 ; C17.2@47.32,42.564 47.206,42.679 C20.2@45.479,42.679 ; R43.1@75.625,64.06 75.95,64.06 v1@77.597,62.413 ; R39.2@77.368,55.207 77.597,55.435 77.597,60.041 ; 77.596,60.042 77.596,60.561 v1(77.597,62.306) v1@77.597,62.413 ; Q9.4@82.392,64.15 82.337,64.094 82.245,64.186 81.759,64.186 81.61,64.037 81.61,63.532 81.154,63.076 81.104,63.076 80.284,62.255 77.755,62.255 v1@77.597,62.413
  Top Layer w0.508: R43.1@75.625,64.06 VBAT_D.1@75.625,66.573
  L3 w0.508: 70.561,66.65 70.714,66.497 v1(74.799,66.497) v1(76.399,66.497)
  other v1: 49.86,1.549 52.129,1.549 54.398,1.549 56.667,1.549 32.055,2.057 49.86,3.277 52.132,3.277 54.404,3.277 56.676,3.277 49.86,5.004 52.129,5.004 54.398,5.004 56.667,5.004 32.055,6.553 49.86,6.604 56.718,6.604 51.537,8.306 54.131,8.306 56.676,8.306 55.506,9.451 52.832,9.728 54,10.871 56.676,10.871 55.347,12.243 50.961,12.866 56.617,13.589 52.603,13.767 50.961,15.686 52.866,15.686 54.771,15.686 50.961,19.126 52.874,19.126 54.787,19.126 56.701,19.126 51.105,21.946 52.976,21.946 54.847,21.946 56.718,21.946 51.105,23.47 52.976,23.47 54.847,23.47 56.718,23.47 51.105,24.994 52.976,24.994 54.847,24.994 56.718,24.994 52.857,26.645 54.788,26.645 56.718,26.645 56.726,28.436 56.54,44.044 51.003,45.568 52.407,45.568 53.81,45.568 55.213,45.568 56.617,45.568 51.003,47.12 52.407,47.12 53.81,47.12 55.213,47.12 56.617,47.12 51.003,48.673 52.407,48.673 53.81,48.673 55.213,48.673 56.617,48.673 51.003,50.216 52.407,50.216 53.81,50.216 55.213,50.216 56.617,50.216 51.003,51.779 52.33,51.779 53.657,51.779 54.985,51.779 56.312,51.779 50.47,54.915 50.546,56.464 51.93,56.464 53.315,56.464 51.93,57.861 50.546,57.887 61.377,68.707 64.092,68.707 66.806,68.707 69.52,68.707 61.377,71.031 64.092,71.031 66.806,71.031 69.52,71.031 61.377,73.355 64.092,73.355 66.806,73.355 69.52,73.355
  other v2: 39.472,7.804 40.957,7.804 40.215,8.23 41.7,8.23 39.472,8.655 40.957,8.655 42.443,8.655 40.215,9.081 41.7,9.081 39.472,9.506 42.443,9.506 40.215,9.931 41.7,9.931 39.472,10.357 40.957,10.357 42.443,10.357 40.215,10.782 41.7,10.782 39.472,11.208 40.957,11.208 42.443,11.208 39.472,26.053 40.957,26.053 42.443,26.053 40.215,26.478 41.7,26.478 39.472,26.904 40.957,26.904 42.443,26.904 40.215,27.329 41.7,27.329 39.472,27.754 42.443,27.754 40.215,28.18 41.7,28.18 39.472,28.605 40.957,28.605 42.443,28.605 40.215,29.031 41.7,29.031 39.472,29.456 40.957,29.456 42.443,29.456 39.472,45.301 40.957,45.301 40.215,45.727 41.7,45.727 39.472,46.152 40.957,46.152 42.443,46.152 40.215,46.577 41.7,46.577 39.472,47.003 42.443,47.003 40.215,47.428 41.7,47.428 39.472,47.854 40.957,47.854 42.443,47.854 40.215,48.279 41.7,48.279 39.472,48.705 40.957,48.705 42.443,48.705 56.648,70.409 57.499,70.409 58.35,70.409 59.201,70.409 60.052,70.409 57.074,71.152 57.925,71.152 58.776,71.152 59.627,71.152 56.648,71.895 57.499,71.895 59.201,71.895 60.052,71.895 57.074,72.638 57.925,72.638 58.776,72.638 59.627,72.638 56.648,73.381 57.499,73.381 58.35,73.381 59.201,73.381 60.052,73.381
  other v4: 40.957,9.506 40.957,27.754 40.957,47.003 58.35,71.895
VBATCP: C38.2 C39.2 C49.2 R43.2 U1.23 VBATCP.1 | length 23.6
  Top Layer w0.254: C49.2@75.143,48.603 75.491,48.255 75.923,48.255 77.175,47.003 C39.2@77.2,47.003 77.225,47.003 81.314,42.914 81.314,42.209 U1.23@81.316,42.207
  Top Layer w0.508: C49.2@75.143,48.703 75.193,48.703 75.514,49.024 75.514,53.075 74.888,53.701 74.161,53.701 73.863,53.998 73.863,56.709 VBATCP.1@75.625,58.471 R43.2@75.625,61.06
VBATD_DIV: C83.2 R87.1 R88.1 R98.1 VBATD_DIV.1 | length 73.1
  Top Layer w0.254: R88.1@82.41,66.116 R98.1@82.41,67.716 82.546,67.852 82.546,68.449 82.753,68.656 87.267,68.656 87.782,68.141 v1(87.782,66.777) 87.782,65.971 87.434,65.623 C83.2@87.427,65.623 ; VBATD_DIV.1@115.189,23.724 115.391,23.724 115.67,24.003 v1(116.408,24.003) 117.678,24.003 R87.1@117.704,24.028
  Bottom Layer w0.254: v1(87.782,66.777) 90.703,66.777 94.005,63.475 100,63.475 116.408,47.066 v1(116.408,24.003)
VBATM: C37.2 R39.1 U1.22 VBATM.1 | length 13.2
  Top Layer w0.254: R39.1@77.403,53.597 77.403,52.439 77.902,51.94 VBATM.1@77.902,51.918 78.005,51.815 78.005,47.903 78.905,47.003 C37.2@78.93,47.003 78.93,46.199 81.816,43.314 U1.22@81.816,42.207
VCAP12: C29.2 C30.2 U1.18 VCAP12.1 | length 16.8
  Top Layer w0.254: U1.18@83.816,42.207 83.816,44.268 85.843,46.296 85.843,46.994 C30.2@85.852,47.003 85.877,47.003 86.657,47.783 86.657,52.053 86.639,52.07 86.639,52.222 C29.2@85.877,52.984 ; C29.2@85.852,52.984 C29.2@85.877,52.984 ; VCAP12.1@86.106,56.896 86.106,56.752 86.657,56.201 86.657,53.764 C29.2@85.877,52.984
VCP: C49.1 R5.1 U1.24 VCP.1 | length 45.3
  Top Layer w0.254: R5.1@67.031,77.356 67.056,77.356 68.106,78.406 69.422,78.406 70.079,77.749 70.079,75.006 72.746,72.339 72.746,52.299 VCP.1@74.244,50.8 74.244,50.608 73.914,50.278 73.914,47.523 74.185,47.252 74.918,47.252 76.146,46.025 77.546,46.025 80.816,42.755 U1.24@80.816,42.207
VDD3: C40.2 C41.2 C72.2 P12.3 R82.1 R96.1 R106.2 R107.2 U1.43 VDD3.1 | length 74.7
  Top Layer w0.254: U1.43@83.816,34.857 83.816,32.627 84.456,31.987 84.456,31.289 C41.2@84.464,31.28 ; C41.2@84.439,31.28 83.66,30.5 83.66,28.402 84.091,27.97 84.091,27.945 C40.2@84.439,27.597 ; C40.2@84.464,27.597 C40.2@84.439,27.597 ; v1(86.944,24.282) 85.928,23.266 VDD3.1@84.363,23.266 ; R96.1@87.208,19.621 87.183,19.621 86.398,20.406 R107.2@86.398,21.311 ; C72.2@94.345,19.621 R82.1@92.491,19.621 92.466,19.621 92.527,19.682 92.527,21.283 91.694,22.115 87.178,22.115 86.398,21.336 R107.2@86.398,21.311 ; VDD3.1@84.363,23.266 83.66,23.97 83.66,26.817 C40.2@84.439,27.597 ; VDD3.1@84.363,23.266 84.363,21.336 R106.2@84.287,21.26 86.347,21.26 R107.2@86.398,21.311
  L3 w0.254: v1(98.146,28.448) 98.146,45.517 v1(98.831,46.203)
  Bottom Layer w0.254: v1(86.944,24.282) 91.11,24.282 95.275,28.448 v1(98.146,28.448) ; P12.3@93.312,53.848 P12.3@93.04,53.848 93.104,53.784 94.171,53.784 98.831,49.124 v1(98.831,46.203)
VDD5: C31.2 C32.2 P12.1 R20.2 R97.1 U1.19 VDD5.1 | length 91.9
  Top Layer w0.254: U1.19@83.316,42.207 83.316,45.064 v1(84.099,45.847) 84.099,46.981 C32.2@84.122,47.003 84.097,47.003 83.317,47.783 83.317,52.205 C31.2@84.097,52.984 ; C31.2@84.122,52.984 C31.2@84.097,52.984 ; R97.1@85.765,67.741 85.867,67.843 v1(87.046,67.843) ; v1(88.646,67.818) v1@88.671,67.793 ; v5(89.891,65.405) 89.891,66.573 v1@88.671,67.793 ; v1(97.815,48.311) 97.815,48.403 97.536,48.683 97.536,60.935 100.787,64.186 117.64,64.186 117.684,64.141 R20.2@117.729,64.186 ; C31.2@84.097,52.984 83.317,53.764 83.317,56.24 VDD5.1@83.972,56.896 83.972,58.305 88.671,63.004 v1@88.671,67.793
  L3 w0.254: v1(84.099,45.847) 86.563,48.311 v1(97.815,48.311)
  Bottom Layer w0.254: v1(87.046,67.843) 87.058,67.831 88.633,67.831 v1(88.646,67.818) ; v5(89.891,65.405) 89.891,64.719 93.04,61.57 P12.1@93.04,58.928
VDD5EXT: C33.2 C84.2 P8.1 P8.2 U1.20 | length 60.3
  Top Layer w0.254: C33.2@82.607,52.75 C33.2@82.372,52.985 82.347,52.985 81.614,52.251 81.593,52.251 81.593,47.783 82.373,47.003 C84.2@82.398,47.003 82.626,46.774 v1(82.626,45.872) 82.626,45.752 82.816,45.562 U1.20@82.816,42.207
  L3 w0.508: v1(82.626,45.872) 83.642,44.856 84.582,44.856 87.173,47.447 124.063,47.447 P8.1@126.086,45.425 P8.2@128.626,45.425
VDD_E: P5.1 P12.2 R12.2 R48.2 | length 68.3
  Top Layer w0.254: v1(102.235,48.565) 102.743,49.073 R48.2@103.619,49.073 ; v1(115.634,82.436) R12.2@115.634,83.591 115.634,83.616 116.49,84.472 121.023,84.472 P5.1@126.086,79.41
  L3 w0.254: v1(102.235,48.565) 103.6,48.565 105.763,50.728 105.763,60.221 115.634,70.091 v1(115.634,82.436)
  Bottom Layer w0.254: P12.2@93.04,56.388 100.863,48.565 v1(102.235,48.565)
VIO: C61.2 R48.1 U3.5 VIO.1 | length 14.2
  Top Layer w0.254: U3.5@103.433,40.716 105.029,40.716 VIO.1@106.248,39.497
  Top Layer w0.508: U3.5@103.433,40.716 102.726,40.716 101.752,41.69 101.752,45.034 103.373,46.655 103.373,47.099 C61.2@103.594,47.32 103.594,47.345 104.998,48.75 104.998,48.852 R48.1@105.219,49.073
VOP: C70.2 C71.2 R96.2 U4.8 U5.8 | length 21.8
  Top Layer w0.254: v1(86.055,18.009) 87.195,18.009 R96.2@87.208,18.021 C70.2@89.057,18.021 89.057,16.73 88.173,15.845 U5.8@88.173,15.117 ; v1(96.952,18.009) 98.093,18.009 C71.2@98.106,18.021 98.106,17.165 99.427,15.845 U4.8@99.427,15.117
  Bottom Layer w0.254: v1(86.055,18.009) v1(96.952,18.009)
VPX_U: C28.1 C43.2 C79.1 P16.1 pad.1@5.918,16.042 Q5.1 Q5.2 Q5.3 Q8.5 R31.1 R37.2 S.1@34.646,10.135 VPX_U.1 | length 65
  Top Layer w0.254: C79.1@20.561,21.7 C43.2@20.561,19.998 20.561,19.973 22.879,17.655 22.879,17.501 23.114,17.266 v2(24.301,17.266) ; Q5.3@36.805,8.865 37.3,8.865 38.015,8.15 v1(38.015,6.568) 38.015,6.555 39.038,5.532 R37.2@39.038,5.207 39.038,4.882 39.486,4.434 40.054,4.434 41.338,3.149 C28.1@41.338,3.124 ; v1(67.947,31.091) 68.068,31.091 68.298,30.861 R31.1@69.288,30.861
  L3 w0.254: v1(38.015,6.568) 38.025,6.579 47.117,6.579 57.633,17.094 57.633,30.99 58.113,31.471 67.568,31.471 v1(67.947,31.091) v1@67.885,31.03
  other v1: 1.52,8.148 5.038,8.148 8.556,8.148 12.074,8.148 15.592,8.148 10.969,12.009 12.163,16.048 10.918,19.553 1.647,22.068 5.191,22.068 8.734,22.068 12.277,22.068 15.82,22.068
  other v2: 24.301,13.862 25.787,13.862 27.273,13.862 25.044,14.288 26.53,14.288 24.301,14.713 25.787,14.713 27.273,14.713 25.044,15.138 26.53,15.138 24.301,15.564 27.273,15.564 25.044,15.989 26.53,15.989 24.301,16.415 25.787,16.415 27.273,16.415 25.044,16.84 26.53,16.84 25.787,17.266 27.273,17.266
  other v3: 6.02,12.409 4.19,12.845 7.822,12.947 2.823,14.138 9.115,14.313 2.286,15.94 9.55,16.143 2.722,17.77 9.013,17.946 4.014,19.136 7.646,19.238 5.817,19.674
  other v4: 25.787,15.564
VPX_U0: C19.2 D3.1 R31.2 U1.36 VPX_U0.1 | length 11.8
  Top Layer w0.254: R31.2@70.888,30.861 70.888,30.886 71.673,31.671 D3.1@72.628,31.671 72.635,31.664 C19.2@74.381,31.664 74.422,31.623 75.573,31.623 VPX_U0.1@76.196,32.246 ; VPX_U0.1@76.26,32.182 76.26,33.385 78.657,35.782 U1.36@79.891,35.782
VPX_V: C27.1 C42.2 C76.1 P15.1 pad.1@5.918,31.017 Q4.1 Q4.2 Q4.3 Q7.5 R33.2 R38.1 S.1@34.646,28.397 VPX_V.1 | length 51.7
  Top Layer w0.254: C76.1@20.561,39.521 C42.2@20.561,37.819 20.561,37.794 22.879,35.477 22.879,35.37 23.114,35.135 v2(24.301,35.135) ; Q4.3@36.805,27.113 36.944,26.973 37.703,26.973 37.946,26.731 37.946,24.601 37.855,24.511 39.038,23.328 R33.2@39.038,23.003 39.038,22.678 39.486,22.23 40.079,22.23 41.338,20.971 C27.1@41.338,20.946 ; v1(68.021,34.595) 68.704,34.595 R38.1@69.288,35.179
  L3 w0.254: v1(37.86,24.511) 37.886,24.486 45.136,24.486 55.651,35.001 67.031,35.001 67.437,34.595 v1(68.021,34.595)
  other v1: 1.723,24.379 5.229,24.379 8.734,24.379 12.239,24.379 15.744,24.379 11.02,27.452 12.264,30.881 11.045,33.98 1.698,37.384 5.26,37.384 8.823,37.384 12.385,37.384 15.947,37.384
  other v2: 24.301,31.731 25.787,31.731 27.273,31.731 25.044,32.156 26.53,32.156 24.301,32.582 25.787,32.582 27.273,32.582 25.044,33.007 26.53,33.007 24.301,33.433 27.273,33.433 25.044,33.858 26.53,33.858 24.301,34.284 25.787,34.284 27.273,34.284 25.044,34.709 26.53,34.709 25.787,35.135 27.273,35.135
  other v3: 6.02,27.385 4.19,27.821 7.822,27.922 2.823,29.113 9.115,29.289 2.286,30.916 9.55,31.119 2.722,32.745 9.013,32.921 4.014,34.112 7.646,34.214 5.817,34.649
  other v4: 25.787,33.433
VPX_V0: C23.2 D4.1 R38.2 U1.33 VPX_V0.1 | length 9.9
  Top Layer w0.254: R38.2@70.888,35.179 70.888,35.204 71.698,36.014 D4.1@72.628,36.014 72.689,35.954 C23.2@74.381,35.954 76.184,35.954 VPX_V0.1@76.26,36.03 77.512,37.282 U1.33@79.891,37.282
VPX_W: C25.2 C26.1 C75.1 P14.1 pad.1@5.918,45.993 Q3.1 Q3.2 Q3.3 Q6.5 R32.2 R44.1 S.1@34.646,47.66 VPX_W.1 | length 48.4
  Top Layer w0.254: C75.1@20.561,57.658 C25.2@20.561,55.956 20.561,55.931 22.879,53.614 22.879,53.238 23.114,53.003 v2(24.301,53.003) ; Q3.3@36.805,46.362 37.3,46.362 37.961,45.701 37.961,44.159 v1(37.922,44.12) 37.998,44.12 39.038,43.08 R32.2@39.038,42.755 39.038,42.587 39.486,42.139 39.871,42.139 41.338,40.672 C26.1@41.338,40.647 ; v1(67.97,40.005) 68.091,40.005 68.226,39.87 68.94,39.87 69.288,39.522 R44.1@69.288,39.497
  L3 w0.254: v1(37.922,44.12) 38.024,44.12 39.624,42.52 65.456,42.52 v1(67.97,40.005)
  other v1: 2.202,39.181 6.258,39.181 10.313,39.181 14.369,39.181 15.951,41.224 1.473,41.935 10.483,41.935 12.261,45.886 1.593,50.204 10.305,50.382 15.893,51.271 3.371,52.973 7.257,52.973 1.803,55.208 5.357,55.208 8.912,55.208 12.466,55.208 16.02,55.208
  other v2: 24.301,49.6 25.787,49.6 27.273,49.6 25.044,50.025 26.53,50.025 24.301,50.451 25.787,50.451 27.273,50.451 25.044,50.876 26.53,50.876 24.301,51.302 27.273,51.302 25.044,51.727 26.53,51.727 24.301,52.153 25.787,52.153 27.273,52.153 25.044,52.578 26.53,52.578 25.787,53.003 27.273,53.003
  other v3: 6.02,42.361 4.19,42.796 7.822,42.898 2.823,44.089 9.115,44.265 2.286,45.891 9.55,46.094 2.722,47.721 9.013,47.897 4.014,49.088 7.646,49.189 5.817,49.625
  other v4: 25.787,51.302
VPX_W0: C24.2 D5.1 R44.2 U1.30 VPX_W0.1 | length 10
  Top Layer w0.254: R44.2@70.888,39.497 71.957,39.497 72.628,40.168 D5.1@72.628,40.358 72.635,40.351 C24.2@74.381,40.351 ; C24.2@74.381,40.272 VPX_W0.1@76.326,40.272 ; VPX_W0.1@76.26,39.878 77.356,38.782 U1.30@79.891,38.782
VS_LOW: R51.1 R52.1 R53.1 R54.1 R55.2 R70.2 R71.2 R89.2 U1.38 VS_LOW.1 | length 365.2
  Top Layer w0.254: v1(39.141,15.672) R53.1@41.7,15.672 ; v1(39.141,54.508) R51.1@41.7,54.508 ; v1(39.15,35.823) 41.691,35.823 R52.1@41.7,35.814 ; R55.2@43.873,35.814 R55.2@43.942,35.814 v1(46.431,35.814) ; v1(78.105,33.503) 78.13,33.477 80.469,33.477 81.314,34.322 81.314,34.855 U1.38@81.316,34.857 ; R54.1@89.854,27.572 89.506,27.224 89.506,26.445 v1(89.51,26.441) 89.573,26.441 90.538,25.476 VS_LOW.1@90.602,25.476 ; R54.1@90.128,27.229 R54.1@90.149,27.229 ; R89.2@92.491,5.194 92.659,5.026 v1(92.659,3.982) ; R71.2@103.057,5.194 103.226,5.026 v1(103.226,3.937) ; R70.2@105.057,19.621 105.057,20.346 105.385,20.674 v1(105.385,20.701)
  L3 w0.254: v1(39.141,15.672) 39.141,15.69 37.389,17.442 37.389,20.156 39.204,21.971 46.595,21.971 56.552,31.928 68.144,31.928 75.77,24.302 86.131,13.941 86.131,8.091 92.009,2.213 100.994,2.213 102.709,3.928 103.217,3.928 v1(103.226,3.937) ; v1(39.15,35.823) 39.15,35.805 39.878,35.077 48.426,35.077 49.264,35.916 68.963,35.916 74.903,29.975 74.903,28.119 90.348,12.675 90.348,5.842 92.193,3.997 92.645,3.997 v1(92.659,3.982) ; v1@39.167,54.534 v1(39.141,54.508) 39.141,54.492 38.481,53.832 38.481,50.292 38.938,49.835 49.124,49.835 49.682,50.394 49.682,52.934 50.292,53.543 56.427,53.543 57.963,52.008 57.963,44.385 58.762,43.586 66.421,43.586 73.33,36.678 77.405,36.678 81.076,33.007 89.675,33.007 98.501,24.181 101.905,24.181 v1(105.385,20.701) ; v1(42.824,35.789) 45.212,35.789 46.812,37.389 69.698,37.389 71.501,35.585 76.022,35.585 v1(78.105,33.503) ; v1(46.431,35.814) 47.447,36.83 69.342,36.83 75.311,30.861 87.3,30.861 89.205,28.956 89.205,26.813 89.51,26.508 v1(89.51,26.441)
  other v1: 39.345,13.259 40.729,13.259 42.139,13.259 43.586,13.259 44.983,13.259 46.38,13.259 47.777,13.259 39.345,14.529 40.538,14.529 43.586,14.726 44.983,14.726 46.38,14.726 47.777,14.726 43.586,16.192 44.983,16.192 46.38,16.192 47.777,16.192 39.345,17.659 40.538,17.659 43.586,17.659 44.983,17.659 46.38,17.659 47.777,17.659 39.345,19.126 40.792,19.126 42.189,19.126 43.586,19.126 44.983,19.126 46.38,19.126 47.777,19.126 39.319,31.521 40.589,31.521 41.783,31.521 42.977,31.521 44.171,31.521 45.364,31.521 46.558,31.521 39.922,32.55 41.129,32.55 42.335,32.55 43.542,32.55 44.748,32.55 45.955,32.55 39.319,33.579 40.526,33.579 41.732,33.579 42.939,33.579 44.145,33.579 45.352,33.579 46.558,33.579 39.345,37.141 40.509,37.141 45.284,37.141 39.395,38.938 40.589,38.938 41.783,38.938 42.977,38.938 44.171,38.938 45.364,38.938 46.558,38.938 39.522,50.622 40.949,50.622 42.376,50.622 43.802,50.622 45.229,50.622 46.656,50.622 48.082,50.622 39.522,52.229 41.038,52.229 42.553,52.229 44.069,52.229 45.585,52.229 47.1,52.229 48.616,52.229 46.787,54.712 48.717,54.737 45.06,54.788 43.358,54.813 39.624,56.185 43.26,56.185 45.077,56.185 46.895,56.185 48.713,56.185 39.645,57.944 41.182,57.944 42.718,57.944 44.255,57.944 45.792,57.944 47.328,57.944 48.865,57.944
XIN: C12.2 R1.1 Y1.1 | length 6
  Top Layer w0.254: C12.2@96.482,32.156 R1.1@96.482,33.782 99.24,33.782 100.291,32.731 Y1.1@100.291,32.631
XOUT: C13.2 R120.1 R123.2 | length 3.7
  Top Layer w0.254: R120.1@96.482,35.433 C13.2@96.482,37.109 98.463,37.109 R123.2@98.489,37.084 R123.2@98.489,37.059
XRSTn: C7.2 R19.1 SW1.3 SW1.4 U1.42 XRSTn.1 | length 89.1
  Top Layer w0.254: v1(81.856,28.42) 81.941,28.335 81.941,27.831 82.509,27.263 XRSTn.1@82.509,27.153 ; v1@81.899,28.426 81.899,30.281 81.899,30.501 82.678,31.28 C7.2@82.703,31.28 82.728,31.28 83.316,31.868 U1.42@83.316,34.857 ; v1(93.918,45.756) 97.053,48.891 97.053,61.099 101.182,65.227 115.087,65.227 v1(116.535,66.675) 117.721,66.675 R19.1@117.729,66.667 ; SW1.3@111.685,77.044 SW1.4@118.185,77.044
  Bottom Layer w0.254: v1(81.856,28.42) 83.062,29.626 84.261,29.626 90.094,35.458 90.094,42.52 93.33,45.756 v1(93.918,45.756) ; v1(116.535,66.675) 116.535,75.394 SW1.4@118.185,77.044
pads on no net: P2.17 P2.18 P2.19 P2.20 SC1.3 SC2.3 SC3.3 SC4.3 U2.3 U2.4 U2.6

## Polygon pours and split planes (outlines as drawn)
GND on Top Layer "GND_L01_P063" (solid, remove dead copper, pour order 63): 71.45,82.855 71.45,7.112 78.511,7.112 80.67,4.953 80.67,0.356 81.001,0.025 122.555,0.025 129.642,7.112 135.103,7.112 135.103,82.855 129.819,82.855 122.733,89.941 80.67,89.941 80.67,85.039 78.486,82.855
VS_LOW on Top Layer "VS_LOW_L01_P011" (solid, remove dead copper, pour order 11): 39.218,58.979 39.141,58.903 39.141,55.397 39.167,55.372 41.123,55.372 41.3,55.194 41.3,53.924 41.148,53.772 38.938,53.772 38.887,53.721 38.887,49.835 47.828,49.835 49.301,51.308 49.301,58.852 49.174,58.979
GND on Top Layer "GND_L01_P059" (solid, remove dead copper, pour order 59): 30.632,89.027 30.632,84.963 28.219,82.55 35.355,82.55 35.738,82.933 35.738,88.748 35.458,89.027
IUS+ on Top Layer "IUS+_L01_P003" (solid, remove dead copper, pour order 3): 28.677,13.259 29.007,12.929 38.405,12.929 38.405,14.91 35.941,14.91 35.916,14.935 35.916,16.231 36.17,16.485 38.405,16.485 38.405,20.168 38.024,20.549 30.734,20.549 28.677,18.491
VBAT_D on Top Layer "VBAT_D_L01_P005" (solid, remove dead copper, pour order 5): 38.938,30.455 38.71,30.226 38.71,24.816 40.462,23.063 45.872,23.063 49.276,19.66 49.276,1.067 58.014,1.067 58.014,28.931 56.49,30.455
IVS+ on Top Layer "IVS+_L01_P007" (solid, remove dead copper, pour order 7): 28.626,36.373 28.626,31.217 29.261,30.582 38.125,30.582 38.43,30.886 38.43,34.9 38.303,35.027 36.17,35.027 35.814,35.382 35.814,36.373 36.068,36.627 38.405,36.627 38.481,36.703 38.481,39.776 37.77,40.488 32.487,40.488 28.88,36.881
IWS+ on Top Layer "IWS+_L01_P010" (solid, remove dead copper, pour order 10): 28.753,54.915 28.753,54.661 28.575,54.483 28.575,49.428 29.185,48.819 32.664,48.819 33.604,49.759 38.608,49.759 38.608,53.67 38.506,53.772 35.89,53.772 35.763,53.899 35.763,54.991 36.144,55.372 38.532,55.372 38.557,55.397 38.557,58.953 38.506,59.004 32.766,59.004 31.521,57.76
VBAT_D on Top Layer "VBAT_D_L01_P012" (solid, remove dead copper, pour order 12): 39.091,49.632 38.735,49.276 38.735,44.526 42.393,40.869 57.252,40.869 57.937,41.554 57.937,60.096 59.004,61.163 71.247,61.163 71.247,73.076 69.901,74.422 51.613,74.422 49.657,72.466 49.657,51.308 47.981,49.632
VBAT1 on Top Layer "VBAT1_L01_P014" (solid, remove dead copper, pour order 14): 36.246,88.468 36.246,73.025 63.729,73.025 65.557,74.854 65.557,88.468
VPX_U on Top Layer "VPX_U_L01_P000" (solid, remove dead copper, pour order 0): 0.762,22.809 24.257,22.809 28.27,18.796 28.27,13.157 29.058,12.37 38.1,12.37 38.1,7.95 37.414,7.264 0.762,7.264
VPX_V on Top Layer "VPX_V_L01_P001" (solid, remove dead copper, pour order 1): 0.483,38.125 26.619,38.125 28.321,36.424 28.321,30.963 29.032,30.251 38.202,30.251 38.354,30.099 38.354,25.603 37.744,24.994 35.865,23.114 0.508,23.114 0.483,23.139
VPX_W on Top Layer "VPX_W_L01_P002" (solid, remove dead copper, pour order 2): 0.864,56.032 27.026,56.032 28.372,54.686 28.372,49.276 28.88,48.768 32.893,48.768 33.401,49.276 38.506,49.276 38.506,46.076 31.191,38.76 0.864,38.76
VS_LOW on Top Layer "VS_LOW_L01_P004" (solid, remove dead copper, pour order 4): 39.268,20.371 38.989,20.091 38.989,16.485 41.123,16.485 41.402,16.205 41.402,15.164 41.148,14.91 38.989,14.91 38.989,12.751 48.235,12.751 48.514,13.03 48.514,20.117 48.26,20.371
VBAT_D on Top Layer "VBAT_D_L01_P006" (solid, remove dead copper, pour order 6): 38.456,11.913 38.456,4.343 41.758,1.041 51.054,1.041 51.054,12.548 49.708,13.894 49.555,13.741 49.555,13.386 48.743,12.573 39.116,12.573
VS_LOW on Top Layer "VS_LOW_L01_P008" (solid, remove dead copper, pour order 8): 39.472,40.107 38.964,39.599 38.964,36.627 41.046,36.627 41.275,36.398 41.275,35.179 41.148,35.052 38.964,35.052 38.964,31.09 39.218,30.836 46.584,30.836 46.939,31.191 46.939,35.052 44.475,35.052 44.171,35.357 44.171,36.449 44.298,36.576 46.939,36.576 46.939,40.056 46.888,40.107
GND on Top Layer "GND_L01_P009" (solid, remove dead copper, pour order 9): 47.625,40.361 47.32,40.056 47.32,36.576 49.581,36.576 49.759,36.398 49.759,35.255 49.555,35.052 47.32,35.052 47.32,31.115 47.65,30.785 56.998,30.785 58.318,29.464 58.318,1.092 59.055,0.356 70.51,0.356 71.298,1.143 71.298,60.706 58.75,60.706 58.318,60.274 58.318,41.224 57.455,40.361
KL30 on Top Layer "KL30_L01_P013" (solid, remove dead copper, pour order 13): 0.203,70.383 0.203,56.515 26.822,56.515 29.845,59.538 49.073,59.538 49.174,59.639 49.174,72.238 48.997,72.415 20.549,72.415 18.669,70.536 0.356,70.536
GND on Top Layer "NONET_L-01_P-001" (solid, remove dead copper, pour order 21): 0.864,82.906 0.381,82.423 0.381,71.704 1.27,70.815 18.263,70.815 20.269,72.822 35.611,72.822 35.789,73 35.789,82.982 25.349,82.982 23.317,85.014 23.317,89.154 7.163,89.154 7.163,85.014 5.055,82.906
VPX_V on Bottom Layer "NONET_L-01_P-001" (solid, remove dead copper, pour order 19): 1.041,38.318 1.041,23.317 28.092,23.317 28.524,23.749 28.524,37.871 28.158,38.238
KL30 on Bottom Layer "NONET_L-01_P-001" (solid, remove dead copper, pour order 32): 1.118,70.587 1.118,56.54 27.711,56.54 28.575,57.404 28.575,60.706 18.669,70.612 1.143,70.612
VPX_W on Bottom Layer "NONET_L-01_P-001" (solid, remove dead copper, pour order 18): 27.915,56.032 1.016,56.032 1.016,38.735 27.94,38.735 28.473,39.268 28.473,55.474
VPX_U on Bottom Layer "NONET_L-01_P-001" (solid, remove dead copper, pour order 20): 1.067,22.809 1.067,7.239 28.092,7.239 28.702,7.849 28.702,22.301 28.194,22.809 27.889,22.809
GND on Bottom Layer "NONET_L-01_P-001" (solid, remove dead copper, pour order 45): 1.041,82.982 1.041,71.069 1.295,70.815 18.415,70.815 20.396,72.796 49.098,72.796 51.765,75.463 51.841,75.387 71.349,75.387 71.349,88.875 70.968,89.256 30.886,89.256 30.632,89.002 30.632,85.014 28.778,83.16 25.222,83.16 23.368,85.014 23.368,89.586 7.137,89.586 7.137,84.988 5.131,82.982
VS_LOW on Bottom Layer "VS_LOW_L04_P015" (solid, remove dead copper, pour order 15): 29.083,57.277 31.039,59.233 49.174,59.233 49.555,58.852 49.555,51.003 48.362,49.809 39.04,49.809 38.405,49.174 38.405,43.434 40.894,40.945 46.584,40.945 48.666,38.862 48.666,32.309 47.346,30.988 39.065,30.988 39.014,31.039 38.405,30.429 38.405,20.955 39.116,20.244 48.542,20.244 49.033,19.752 49.022,19.741 49.022,13.03 48.438,12.446 30.912,12.446 29.083,14.275
GND on Bottom Layer "GND_L04_P066" (solid, remove dead copper, pour order 66): 70.663,47.371 70.663,32.08 73.05,32.08 73.05,47.371
VBAT_D on Bottom Layer "NONET_L-01_P-001" (solid, remove dead copper, pour order 17): 49.657,58.885 49.657,50.8 48.514,49.657 39.218,49.657 38.837,49.276 38.837,43.459 41.097,41.199 47.066,41.199 48.971,39.294 48.971,31.902 47.777,30.709 39.167,30.709 38.633,30.175 38.633,21.285 39.268,20.65 48.616,20.65 49.276,19.99 49.276,12.979 48.539,12.243 31.318,12.243 30.632,11.557 30.632,1.626 31.217,1.041 57.887,1.041 57.988,1.143 57.988,58.869
VBAT_D on Bottom Layer "VBAT_D_L04_P068" (solid, remove dead copper, pour order 68): 55.016,74.803 71.349,74.803 71.425,74.727 71.425,68.224 71.069,67.869 55.016,67.869
GND on Bottom Layer "GND_L04_P069" (solid, remove dead copper, pour order 69): 17.247,72.619 17.247,72.339 30.15,59.436 52.095,59.436 58.42,53.111 66.246,53.111 71.247,58.112 71.247,67.691 71.044,67.894 62.332,67.894 53.95,76.276 19.863,76.276 18.821,75.235
GND on Bottom Layer "NONET_L-01_P-001" (solid, remove dead copper, pour order 31): 58.268,60.3 58.268,1.118 58.445,0.94 71.069,0.94 71.247,1.118 71.247,60.808 58.776,60.808
GND on Bottom Layer "GND_L04_P065" (solid, remove dead copper, pour order 65): 71.526,82.855 71.374,7.112 78.511,7.112 80.67,4.953 80.67,0.356 81.001,0.025 126.086,0.025 127.838,1.778 127.838,5.08 129.87,7.112 135.103,7.112 135.103,82.855 129.997,82.855 127.838,85.014 127.838,88.646 126.543,89.941 80.67,89.941 80.67,85.039 78.486,82.855
GND on L3 "NONET_L-01_P-001" (solid, remove dead copper, pour order 34): 0.965,82.931 0.965,71.069 1.092,70.942 18.567,70.942 20.726,73.101 35.408,73.101 35.789,73.482 35.789,87.198 34.372,88.615 28.791,83.16 25.222,83.16 23.368,85.014 23.368,89.306 7.163,89.306 7.163,85.039 5.055,82.931
VPX_U on L3 "VPX_U_L03_P047" (solid, remove dead copper, pour order 47): 23.876,17.755 23.876,13.335 27.838,13.335 27.838,17.755
VPX_V on L3 "VPX_V_L03_P048" (solid, remove dead copper, pour order 48): 23.876,35.623 23.876,31.204 27.838,31.204 27.838,35.623
VPX_W on L3 "VPX_W_L03_P049" (solid, remove dead copper, pour order 49): 23.876,53.492 23.876,49.073 27.838,49.073 27.838,53.492
KL30 on L3 "KL30_L03_P053" (solid, remove dead copper, pour order 53): 1.118,70.637 1.067,70.587 1.067,56.54 16.332,56.54 16.535,56.744 16.535,70.358 16.256,70.637
VPX_W on L3 "VPX_W_L03_P054" (solid, remove dead copper, pour order 54): 1.041,56.032 1.041,38.684 16.612,38.684 16.713,38.786 16.713,55.905 16.586,56.032
VPX_V on L3 "VPX_V_L03_P055" (solid, remove dead copper, pour order 55): 1.067,38.252 1.067,23.317 16.637,23.317 16.739,23.419 16.739,37.973 16.459,38.252
VPX_U on L3 "VPX_U_L03_P056" (solid, remove dead copper, pour order 56): 1.041,22.733 1.041,7.163 16.535,7.163 16.662,7.29 16.662,22.682 16.485,22.86 1.168,22.86
GND on L3 "GND_L03_P060" (solid, remove dead copper, pour order 60): 30.582,89.51 30.582,84.328 32.918,84.328 35.789,87.198 35.789,89.256 35.535,89.51
VS_LOW on L3 "VS_LOW_L03_P046" (solid, remove dead copper, pour order 46): 38.354,19.71 38.354,12.7 38.532,12.522 48.006,12.522 48.59,13.106 48.59,19.837 47.549,20.879 39.548,20.879 38.76,20.091
VBAT1 on L3 "NONET_L-01_P-001" (solid, remove dead copper, pour order 33): 36.246,88.316 36.246,73.508 50.013,73.508 51.74,75.235 71.145,75.235 71.145,88.316
VS_LOW on L3 "NONET_L-01_P-001" (solid, remove dead copper, pour order 23): 37.287,58.674 36.601,57.988 36.601,55.987 37.135,55.453 39.446,55.453 39.807,55.093 39.807,53.97 39.04,53.203 39.04,50.622 39.395,50.267 48.565,50.267 49.2,50.902 49.2,58.471 48.997,58.674
VS_LOW on L3 "NONET_L-01_P-001" (solid, remove dead copper, pour order 24): 37.948,40.462 37.338,40.462 36.881,40.005 36.881,32.029 38.202,30.709 47.93,30.709 49.251,32.029 49.251,39.802 48.618,40.434
VBAT_D on L3 "VBAT_D_L03_P050" (solid, remove dead copper, pour order 50): 17.297,71.044 16.942,70.688 16.942,7.29 17.043,7.188 28.931,7.188 30.658,5.461 30.658,1.549 31.293,0.914 31.318,0.94 56.464,0.94 57.074,1.549 57.074,60.503 58.064,61.493 70.917,61.493 71.171,61.747 71.171,74.549 51.46,74.549 49.809,72.898 19.152,72.898
GND on L3 "GND_L03_P051" (solid, remove dead copper, pour order 51): 57.785,60.3 57.785,1.27 57.988,1.067 71.171,1.067 71.323,1.219 71.298,1.245 71.298,61.036 58.522,61.036
GND on L3 "GND_L03_P064" (solid, remove dead copper, pour order 64): 71.526,82.855 71.526,7.112 78.511,7.112 80.67,4.953 80.67,0.356 81.001,0.025 126.086,0.025 127.838,1.778 127.838,5.08 129.87,7.112 135.103,7.112 135.103,82.855 129.997,82.855 127.838,85.014 127.838,88.646 126.543,89.941 80.67,89.941 80.67,85.039 78.486,82.855
VPX_W on GND "NONET_L-01_P-001" (solid, remove dead copper, pour order 35): 23.774,53.518 23.774,49.149 27.737,49.149 27.737,53.518
VPX_V on GND "NONET_L-01_P-001" (solid, remove dead copper, pour order 36): 23.774,35.649 23.774,31.28 27.737,31.28 27.737,35.649
VPX_U on GND "NONET_L-01_P-001" (solid, remove dead copper, pour order 37): 23.774,17.78 23.774,13.411 27.737,13.411 27.737,17.78
VBAT_D on GND "NONET_L-01_P-001" (solid, remove dead copper, pour order 38): 38.151,12.065 37.744,11.659 37.744,7.366 38.43,6.68 46.33,6.68 48.717,9.068 48.717,12.065
VBAT_D on GND "NONET_L-01_P-001" (solid, remove dead copper, pour order 41): 39.116,29.87 39.116,25.73 42.901,25.73 42.901,29.87
VBAT_D on GND "NONET_L-01_P-001" (solid, remove dead copper, pour order 42): 39.116,49.119 39.116,44.979 42.901,44.979 42.901,49.119
VBAT_D on GND "NONET_L-01_P-001" (solid, remove dead copper, pour order 44): 56.234,70.053 60.374,70.053 60.374,73.838 56.234,73.838
VS_LOW on GND "VS_LOW_L02_P016" (solid, remove dead copper, pour order 16): 29.083,57.861 30.455,59.233 49.174,59.233 50.013,58.395 50.013,13.513 48.946,12.446 30.912,12.446 29.083,14.275
GND on GND "NONET_L-01_P-001" (solid, remove dead copper, pour order 43): 1.092,82.906 1.092,7.442 1.372,7.163 29.032,7.163 30.937,5.258 30.937,1.397 31.369,0.965 71.069,0.965 71.247,1.143 71.247,89.51 31.115,89.51 30.582,88.976 30.582,84.938 28.804,83.16 25.171,83.16 23.343,84.988 23.343,88.646 22.377,89.611 7.569,89.611 7.163,89.205 7.163,85.039 5.105,82.982 1.168,82.982
GND on GND "GND_L02_P062" (solid, remove dead copper, pour order 62): 71.577,82.855 71.425,7.112 78.511,7.112 80.67,4.953 80.67,0.356 81.001,0.025 126.086,0.025 127.838,1.778 127.838,5.08 129.87,7.112 135.103,7.112 135.103,82.855 129.997,82.855 127.838,85.014 127.838,88.646 126.543,89.941 80.67,89.941 80.67,85.039 78.486,82.855

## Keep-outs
Keep-Out Layer:
  circle w0.15: c27,86.5 r1.75
  circle w0.15: c77,86.5 r1.75
  circle w0.15: c77,3.5 r1.75
  circle w0.15: c27,3.5 r1.75
  lines w0.1: 0,3.448 ccw(c3.5,3.5) 3.5,0 ; 0,86.5 cw(c3.5,86.5) 3.448,90 ; 131.5,90 cw(c131.5,86.5) 135,86.552 ; 131.552,0 ccw(c131.5,3.5) 135,3.5 ; 0,0 135,0 135,90 0,90 0,0
  lines w0.2: 0,0 0,90 135,90 135,0 0,0

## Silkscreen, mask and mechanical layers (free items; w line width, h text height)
Top Overlay:
  drawing of 1566 lines, arcs and shapes, not listed
  text "VBAT1" at 42.34,88.517 h1
  text "GND" at 116.203,88.441 h1
  text "VBAT" at 101.471,88.416 h1
  text "VDD_E" at 120.09,79.072 h1
  text "BOOT" at 130.3,78.916 h1
  text "EVB_SPD1177/SPD1179B_QFN48_V01" at 76.071,77.954 h1
  text "20241112" at 85.342,76.376 h1
  text "TRSTn" at 120.466,76.352 h1
  text "GND" at 130.3,76.352 h1
  text "GND" at 19.508,74.747 h2 r90
  text "TDI" at 122.666,73.787 h1
  text "GND" at 130.3,73.787 h1
  text "SWD" at 121.532,71.222 h1
  text "RX" at 130.3,71.222 h1
  text "SWC" at 121.485,68.657 h1
  text "TX" at 130.3,68.657 h1
  text "TDO" at 121.904,66.093 h1
  text "XRSTn" at 130.3,66.093 h1
  text "VDD5" at 121.004,63.528 h1
  text "GND" at 130.3,63.528 h1
  text "VBAT_IN" at 19.485,60.627 h2 r90
  text "VDD5" at 94.715,58.52 h0.8
  text "5VCOM" at 125.046,56.336 h1 r90
  text "VDD_E" at 94.588,55.961 h0.8
  text "VDD3" at 94.715,53.364 h0.8
  text "CANH" at 130.529,53.211 h1
  text "CANL" at 130.577,50.544 h1
  text "VDD5EXT" at 124.357,47.395 h1
  text "W" at 19.507,45.168 h2 r90
  text "PWM/LIN" at 124.636,42.229 h1
  text "IO12" at 121.87,34.441 h1
  text "LED2" at 130.275,34.441 h1
  text "IO13" at 121.87,31.89 h1
  text "LED1" at 130.275,31.89 h1
  text "V" at 19.507,30.432 h2 r90
  text "IO14" at 121.823,29.338 h1
  text "MCUFG" at 130.275,29.338 h1
  text "ADC4" at 120.88,26.787 h1
  text "D2S" at 130.275,26.787 h1
  text "IDC/-" at 130.275,24.378 h1
  text "ADC3" at 120.928,24.236 h1
  text "IW/-" at 130.275,21.827 h1
  text "ADC2" at 120.928,21.684 h1
  text "ADC1" at 121.356,19.133 h1
  text "IV" at 130.275,19.133 h1
  text "ADC0" at 120.928,16.582 h1
  text "IU" at 130.275,16.582 h1
  text "U" at 19.485,15.538 h2 r90
  text "NC" at 122.818,14.03 h1
  text "NC" at 130.275,14.03 h1
  text "NC" at 122.818,11.479 h1
  text "NC" at 130.275,11.479 h1
  text "VBAT" at 71.982,10.539 h1
  text "MON" at 76.021,10.539 h1
  text "GND" at 79.602,10.539 h1
  text "GND" at 115.848,2.767 h1
Bottom Solder:
  rectangle: 55.804,69.266 60.858,74.295
  rectangle: 22.955,48.654 28.01,53.683
  rectangle: 39.211,44.285 44.266,49.314
  rectangle: 22.955,30.785 28.01,35.814
  rectangle: 22.955,12.916 28.01,17.945
  rectangle: 39.211,25.036 44.266,30.066
Mechanical 1:
  circle w0.15: c77,86.5 r1.75
  circle w0.15: c77,3.5 r1.75
  circle w0.15: c27,3.5 r1.75
  circle w0.15: c27,86.5 r1.75
  lines w0.1: 0,3.448 ccw(c3.5,3.5) 3.5,0 ; 0,86.5 cw(c3.5,86.5) 3.448,90 ; 131.5,90 cw(c131.5,86.5) 135,86.552 ; 131.552,0 ccw(c131.5,3.5) 135,3.5 ; 0,0 0,90 135,90 135,0 0,0
  lines w0.2: 0,0 0,90 135,90 135,0 0,0
Mechanical 15:
  lines w0.1: 26.746,3.5 27,3.5 ; 26.8,86.5 27,86.5 ; 27,3.266 27,3.5 ; 27,3.734 27,3.5 ; 27,86.266 27,86.5 ; 27,86.72 27,86.5 ; 27.254,3.5 27,3.5 ; 27.254,86.5 27,86.5 ; 76.766,3.5 77,3.5 ; 76.766,86.5 77,86.5 ; 77,3.246 77,3.5 ; 77,3.734 77,3.5 ; 77,86.246 77,86.5 ; 77,86.8 77,86.5 ; 77.25,86.5 77,86.5 ; 77.272,3.5 77,3.5 ; 84.5,0 19.5,0 19.5,90 84.5,90 ; 84.502,-0.051 84.602,89.949
  lines w0.254: 120.269,-0.102 120.269,89.713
